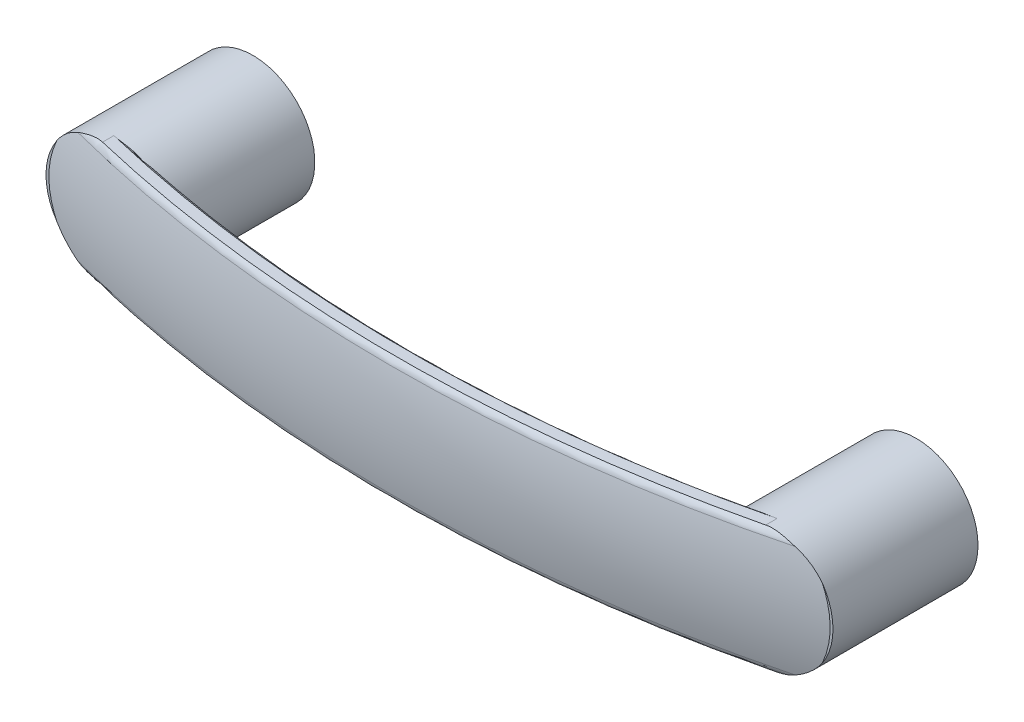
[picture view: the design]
ISO-10303-21;
HEADER;
FILE_DESCRIPTION(('STEP AP214'),'2;1');
FILE_NAME('part.step','',(''),(''),'','','');
FILE_SCHEMA(('AUTOMOTIVE_DESIGN { 1 0 10303 214 1 1 1 1 }'));
ENDSEC;
DATA;
#1=APPLICATION_CONTEXT('core data for automotive mechanical design processes');
#2=APPLICATION_PROTOCOL_DEFINITION('international standard','automotive_design',2000,#1);
#3=PRODUCT_CONTEXT('',#1,'mechanical');
#4=PRODUCT('Part','Part','',(#3));
#5=PRODUCT_RELATED_PRODUCT_CATEGORY('part','',(#4));
#6=PRODUCT_DEFINITION_FORMATION('','',#4);
#7=PRODUCT_DEFINITION_CONTEXT('part definition',#1,'design');
#8=PRODUCT_DEFINITION('design','',#6,#7);
#9=PRODUCT_DEFINITION_SHAPE('','',#8);
#10=(LENGTH_UNIT() NAMED_UNIT(*) SI_UNIT(.MILLI.,.METRE.));
#11=(NAMED_UNIT(*) PLANE_ANGLE_UNIT() SI_UNIT($,.RADIAN.));
#12=(NAMED_UNIT(*) SI_UNIT($,.STERADIAN.) SOLID_ANGLE_UNIT());
#13=UNCERTAINTY_MEASURE_WITH_UNIT(LENGTH_MEASURE(1.E-05),#10,'distance_accuracy_value','');
#14=(GEOMETRIC_REPRESENTATION_CONTEXT(3) GLOBAL_UNCERTAINTY_ASSIGNED_CONTEXT((#13)) GLOBAL_UNIT_ASSIGNED_CONTEXT((#10,
#11,#12)) REPRESENTATION_CONTEXT('',''));
#15=CARTESIAN_POINT('',(0.,0.,0.));
#16=DIRECTION('',(0.,0.,1.));
#17=DIRECTION('',(1.,0.,0.));
#18=AXIS2_PLACEMENT_3D('',#15,#16,#17);
#19=CARTESIAN_POINT('',(-0.255140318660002,0.,0.));
#20=DIRECTION('',(0.,0.,1.));
#21=DIRECTION('',(0.,-1.,0.));
#22=AXIS2_PLACEMENT_3D('',#19,#20,#21);
#23=PLANE('',#22);
#24=CARTESIAN_POINT('',(0.,0.,0.));
#25=DIRECTION('',(0.,0.,-1.));
#26=DIRECTION('',(-1.,0.,0.));
#27=AXIS2_PLACEMENT_3D('',#24,#25,#26);
#28=CIRCLE('',#27,4.);
#29=CARTESIAN_POINT('',(-4.,0.,0.));
#30=VERTEX_POINT('',#29);
#31=EDGE_CURVE('E339',#30,#30,#28,.T.);
#32=ORIENTED_EDGE('',*,*,#31,.F.);
#33=EDGE_LOOP('',(#32));
#34=FACE_BOUND('',#33,.T.);
#35=CARTESIAN_POINT('',(0.,0.,0.));
#36=DIRECTION('',(0.,0.,1.));
#37=DIRECTION('',(-1.,0.,0.));
#38=AXIS2_PLACEMENT_3D('',#35,#36,#37);
#39=CIRCLE('',#38,14.);
#40=CARTESIAN_POINT('',(-14.,0.,0.));
#41=VERTEX_POINT('',#40);
#42=EDGE_CURVE('E210',#41,#41,#39,.T.);
#43=ORIENTED_EDGE('',*,*,#42,.F.);
#44=EDGE_LOOP('',(#43));
#45=FACE_BOUND('',#44,.T.);
#46=ADVANCED_FACE('F14',(#34,#45),#23,.F.);
#47=CARTESIAN_POINT('',(-0.255140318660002,0.,32.8));
#48=DIRECTION('',(0.,0.,1.));
#49=DIRECTION('',(0.,-1.,0.));
#50=AXIS2_PLACEMENT_3D('',#47,#48,#49);
#51=PLANE('',#50);
#52=CARTESIAN_POINT('',(0.,0.,32.8));
#53=DIRECTION('',(0.,0.,1.));
#54=DIRECTION('',(1.,0.,0.));
#55=AXIS2_PLACEMENT_3D('',#52,#53,#54);
#56=CIRCLE('',#55,14.);
#57=CARTESIAN_POINT('',(-11.5953620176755,-7.84522655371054,32.8));
#58=VERTEX_POINT('',#57);
#59=CARTESIAN_POINT('',(-11.5953620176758,7.8452265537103,32.8));
#60=VERTEX_POINT('',#59);
#61=EDGE_CURVE('E9',#58,#60,#56,.F.);
#62=ORIENTED_EDGE('',*,*,#61,.F.);
#63=CARTESIAN_POINT('',(-13.3490803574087,1.41218032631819E-13,32.8));
#64=CARTESIAN_POINT('',(-13.3490709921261,-0.569935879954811,32.8));
#65=CARTESIAN_POINT('',(-13.3215830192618,-1.14012000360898,32.8));
#66=CARTESIAN_POINT('',(-13.2123860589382,-2.27554882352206,32.8));
#67=CARTESIAN_POINT('',(-13.1306350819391,-2.84078935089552,32.8));
#68=CARTESIAN_POINT('',(-12.9149496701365,-3.9626413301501,32.8));
#69=CARTESIAN_POINT('',(-12.7808871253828,-4.51922808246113,32.8));
#70=CARTESIAN_POINT('',(-12.464044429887,-5.61855917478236,32.8));
#71=CARTESIAN_POINT('',(-12.2812397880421,-6.16129640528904,32.8));
#72=CARTESIAN_POINT('',(-11.8733813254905,-7.2239957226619,32.8));
#73=CARTESIAN_POINT('',(-11.648794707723,-7.74413795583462,32.8));
#74=CARTESIAN_POINT('',(-11.1605291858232,-8.76583164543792,32.8));
#75=CARTESIAN_POINT('',(-10.896833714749,-9.2673751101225,32.8));
#76=CARTESIAN_POINT('',(-10.0541492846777,-10.7414126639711,32.8));
#77=CARTESIAN_POINT('',(-9.42309640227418,-11.684483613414,32.8));
#78=CARTESIAN_POINT('',(-8.14542950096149,-13.3693211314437,32.8));
#79=CARTESIAN_POINT('',(-7.51184390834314,-14.1212333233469,32.8));
#80=CARTESIAN_POINT('',(-6.18084712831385,-15.5669262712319,32.8));
#81=CARTESIAN_POINT('',(-5.48339382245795,-16.2606680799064,32.8));
#82=CARTESIAN_POINT('',(-4.03645149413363,-17.5950112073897,32.8));
#83=CARTESIAN_POINT('',(-3.28683177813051,-18.2354695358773,32.8));
#84=CARTESIAN_POINT('',(-1.74707423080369,-19.4660253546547,32.8));
#85=CARTESIAN_POINT('',(-0.956920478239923,-20.056102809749,32.8));
#86=CARTESIAN_POINT('',(0.604773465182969,-21.1541493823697,32.8));
#87=CARTESIAN_POINT('',(1.37433478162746,-21.6649507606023,32.8));
#88=CARTESIAN_POINT('',(2.93671257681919,-22.6492343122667,32.8));
#89=CARTESIAN_POINT('',(3.72952536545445,-23.1227223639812,32.8));
#90=CARTESIAN_POINT('',(5.33522483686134,-24.0359010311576,32.8));
#91=CARTESIAN_POINT('',(6.14812840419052,-24.475561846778,32.8));
#92=CARTESIAN_POINT('',(7.79019304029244,-25.3233754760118,32.8));
#93=CARTESIAN_POINT('',(8.61935474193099,-25.7315270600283,32.8));
#94=CARTESIAN_POINT('',(10.2927492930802,-26.5193919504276,32.8));
#95=CARTESIAN_POINT('',(11.1370051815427,-26.899056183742,32.8));
#96=CARTESIAN_POINT('',(12.837113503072,-27.6313371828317,32.8));
#97=CARTESIAN_POINT('',(13.6929656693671,-27.9839545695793,32.8));
#98=CARTESIAN_POINT('',(15.4142797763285,-28.6639496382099,32.8));
#99=CARTESIAN_POINT('',(16.2797383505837,-28.9913358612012,32.8));
#100=CARTESIAN_POINT('',(18.0191662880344,-29.6227044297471,32.8));
#101=CARTESIAN_POINT('',(18.89313597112,-29.9266858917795,32.8));
#102=CARTESIAN_POINT('',(20.729997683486,-30.5399909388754,32.8));
#103=CARTESIAN_POINT('',(21.6936011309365,-30.8471826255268,32.8));
#104=CARTESIAN_POINT('',(23.6282781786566,-31.4371256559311,32.8));
#105=CARTESIAN_POINT('',(24.5993521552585,-31.7198757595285,32.8));
#106=CARTESIAN_POINT('',(27.522440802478,-32.5338826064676,32.8));
#107=CARTESIAN_POINT('',(29.4840840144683,-33.0308173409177,32.8));
#108=CARTESIAN_POINT('',(33.4278863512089,-33.9436771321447,32.8));
#109=CARTESIAN_POINT('',(35.4100635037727,-34.3595232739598,32.8));
#110=CARTESIAN_POINT('',(39.3882486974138,-35.1174744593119,32.8));
#111=CARTESIAN_POINT('',(41.3842557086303,-35.4595849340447,32.8));
#112=CARTESIAN_POINT('',(45.3917301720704,-36.0770097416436,32.8));
#113=CARTESIAN_POINT('',(47.4032241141,-36.3521509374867,32.8));
#114=CARTESIAN_POINT('',(51.4338330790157,-36.8392239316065,32.8));
#115=CARTESIAN_POINT('',(53.4529482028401,-37.0511548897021,32.8));
#116=CARTESIAN_POINT('',(57.4954781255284,-37.4152116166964,32.8));
#117=CARTESIAN_POINT('',(59.5188901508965,-37.5673683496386,32.8));
#118=CARTESIAN_POINT('',(63.5691860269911,-37.8144735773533,32.8));
#119=CARTESIAN_POINT('',(65.5960698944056,-37.9094217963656,32.8));
#120=CARTESIAN_POINT('',(69.9667812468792,-38.0540495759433,32.8));
#121=CARTESIAN_POINT('',(72.3109211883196,-38.0944031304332,32.8));
#122=CARTESIAN_POINT('',(76.9993547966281,-38.1016218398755,32.8));
#123=CARTESIAN_POINT('',(79.3436484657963,-38.0684852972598,32.8));
#124=CARTESIAN_POINT('',(84.0314425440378,-37.9279830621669,32.8));
#125=CARTESIAN_POINT('',(86.3749416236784,-37.8205726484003,32.8));
#126=CARTESIAN_POINT('',(91.0571697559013,-37.5292164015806,32.8));
#127=CARTESIAN_POINT('',(93.3958989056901,-37.3452721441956,32.8));
#128=CARTESIAN_POINT('',(98.063191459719,-36.8971222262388,32.8));
#129=CARTESIAN_POINT('',(100.39176300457,-36.633001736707,32.8));
#130=CARTESIAN_POINT('',(105.037852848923,-36.0185447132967,32.8));
#131=CARTESIAN_POINT('',(107.355370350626,-35.6682020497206,32.8));
#132=CARTESIAN_POINT('',(110.818275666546,-35.0720785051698,32.8));
#133=CARTESIAN_POINT('',(111.969830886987,-34.8617135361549,32.8));
#134=CARTESIAN_POINT('',(114.268106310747,-34.4161123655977,32.8));
#135=CARTESIAN_POINT('',(115.414826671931,-34.1808769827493,32.8));
#136=CARTESIAN_POINT('',(117.702376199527,-33.6841023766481,32.8));
#137=CARTESIAN_POINT('',(118.843206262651,-33.4225672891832,32.8));
#138=CARTESIAN_POINT('',(121.118039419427,-32.8714640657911,32.8));
#139=CARTESIAN_POINT('',(122.252042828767,-32.5818972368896,32.8));
#140=CARTESIAN_POINT('',(124.455555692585,-31.9879558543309,32.8));
#141=CARTESIAN_POINT('',(125.525458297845,-31.6850425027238,32.8));
#142=CARTESIAN_POINT('',(127.656605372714,-31.0501791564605,32.8));
#143=CARTESIAN_POINT('',(128.71785008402,-30.7182299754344,32.8));
#144=CARTESIAN_POINT('',(130.83057501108,-30.0228805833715,32.8));
#145=CARTESIAN_POINT('',(131.882050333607,-29.6594654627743,32.8));
#146=CARTESIAN_POINT('',(133.97269434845,-28.8987348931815,32.8));
#147=CARTESIAN_POINT('',(135.011863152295,-28.5014197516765,32.8));
#148=CARTESIAN_POINT('',(137.069942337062,-27.6720906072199,32.8));
#149=CARTESIAN_POINT('',(138.088930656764,-27.2402706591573,32.8));
#150=CARTESIAN_POINT('',(140.109212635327,-26.3366853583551,32.8));
#151=CARTESIAN_POINT('',(141.110504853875,-25.8649167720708,32.8));
#152=CARTESIAN_POINT('',(143.090291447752,-24.878045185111,32.8));
#153=CARTESIAN_POINT('',(144.068808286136,-24.3629874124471,32.8));
#154=CARTESIAN_POINT('',(145.998777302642,-23.2847161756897,32.8));
#155=CARTESIAN_POINT('',(146.950236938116,-22.7215161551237,32.8));
#156=CARTESIAN_POINT('',(148.55229757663,-21.710373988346,32.8));
#157=CARTESIAN_POINT('',(149.211155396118,-21.275504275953,32.8));
#158=CARTESIAN_POINT('',(150.508585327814,-20.376436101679,32.8));
#159=CARTESIAN_POINT('',(151.147158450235,-19.9122391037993,32.8));
#160=CARTESIAN_POINT('',(152.40114019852,-18.951580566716,32.8));
#161=CARTESIAN_POINT('',(153.016513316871,-18.4550725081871,32.8));
#162=CARTESIAN_POINT('',(154.21836783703,-17.4280855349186,32.8));
#163=CARTESIAN_POINT('',(154.804848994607,-16.8976063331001,32.8));
#164=CARTESIAN_POINT('',(155.94890990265,-15.7947763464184,32.8));
#165=CARTESIAN_POINT('',(156.506130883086,-15.222051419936,32.8));
#166=CARTESIAN_POINT('',(157.57775105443,-14.0374719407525,32.8));
#167=CARTESIAN_POINT('',(158.092144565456,-13.425612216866,32.8));
#168=CARTESIAN_POINT('',(159.067967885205,-12.1627900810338,32.8));
#169=CARTESIAN_POINT('',(159.529504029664,-11.5119103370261,32.8));
#170=CARTESIAN_POINT('',(160.390010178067,-10.1700444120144,32.8));
#171=CARTESIAN_POINT('',(160.789013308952,-9.47907973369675,32.8));
#172=CARTESIAN_POINT('',(161.396300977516,-8.28741752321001,32.8));
#173=CARTESIAN_POINT('',(161.624674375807,-7.79691203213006,32.8));
#174=CARTESIAN_POINT('',(162.043253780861,-6.79992921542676,32.8));
#175=CARTESIAN_POINT('',(162.233470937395,-6.29345660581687,32.8));
#176=CARTESIAN_POINT('',(162.57191600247,-5.267023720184,32.8));
#177=CARTESIAN_POINT('',(162.720174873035,-4.74707370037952,32.8));
#178=CARTESIAN_POINT('',(162.971585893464,-3.69631165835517,32.8));
#179=CARTESIAN_POINT('',(163.074737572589,-3.16549952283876,32.8));
#180=CARTESIAN_POINT('',(163.233854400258,-2.09362456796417,32.8));
#181=CARTESIAN_POINT('',(163.289539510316,-1.55251990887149,32.8));
#182=CARTESIAN_POINT('',(163.351218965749,-0.467470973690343,32.8));
#183=CARTESIAN_POINT('',(163.35721356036,0.0764732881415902,32.8));
#184=CARTESIAN_POINT('',(163.319348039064,1.16269814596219,32.8));
#185=CARTESIAN_POINT('',(163.275479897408,1.70497846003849,32.8));
#186=CARTESIAN_POINT('',(163.139047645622,2.78334261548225,32.8));
#187=CARTESIAN_POINT('',(163.046484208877,3.31942654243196,32.8));
#188=CARTESIAN_POINT('',(162.823369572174,4.34313329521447,32.8));
#189=CARTESIAN_POINT('',(162.696036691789,4.83146438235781,32.8));
#190=CARTESIAN_POINT('',(162.403985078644,5.79694207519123,32.8));
#191=CARTESIAN_POINT('',(162.239254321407,6.27408502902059,32.8));
#192=CARTESIAN_POINT('',(161.875391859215,7.21499047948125,32.8));
#193=CARTESIAN_POINT('',(161.676261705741,7.67875357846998,32.8));
#194=CARTESIAN_POINT('',(161.246701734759,8.59159576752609,32.8));
#195=CARTESIAN_POINT('',(161.016264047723,9.04067113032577,32.8));
#196=CARTESIAN_POINT('',(160.388824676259,10.1729247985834,32.8));
#197=CARTESIAN_POINT('',(159.971344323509,10.8448156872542,32.8));
#198=CARTESIAN_POINT('',(159.078525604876,12.1490720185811,32.8));
#199=CARTESIAN_POINT('',(158.603154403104,12.781414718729,32.8));
#200=CARTESIAN_POINT('',(157.603341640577,14.0083401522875,32.8));
#201=CARTESIAN_POINT('',(157.07878510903,14.6028286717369,32.8));
#202=CARTESIAN_POINT('',(155.989992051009,15.7538584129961,32.8));
#203=CARTESIAN_POINT('',(155.425762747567,16.3104065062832,32.8));
#204=CARTESIAN_POINT('',(154.346576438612,17.3115185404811,32.8));
#205=CARTESIAN_POINT('',(153.835951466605,17.7607820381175,32.8));
#206=CARTESIAN_POINT('',(152.793861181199,18.6345171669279,32.8));
#207=CARTESIAN_POINT('',(152.262392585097,19.0589848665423,32.8));
#208=CARTESIAN_POINT('',(150.640746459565,20.2978002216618,32.8));
#209=CARTESIAN_POINT('',(149.523733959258,21.0771911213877,32.8));
#210=CARTESIAN_POINT('',(147.23529441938,22.554585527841,32.8));
#211=CARTESIAN_POINT('',(146.063781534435,23.2524541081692,32.8));
#212=CARTESIAN_POINT('',(143.680776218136,24.5751352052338,32.8));
#213=CARTESIAN_POINT('',(142.469292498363,25.1999635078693,32.8));
#214=CARTESIAN_POINT('',(139.971181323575,26.4062983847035,32.8));
#215=CARTESIAN_POINT('',(138.683418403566,26.9854383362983,32.8));
#216=CARTESIAN_POINT('',(136.081761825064,28.0821553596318,32.8));
#217=CARTESIAN_POINT('',(134.767862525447,28.5997189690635,32.8));
#218=CARTESIAN_POINT('',(132.11853748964,29.5799471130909,32.8));
#219=CARTESIAN_POINT('',(130.783093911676,30.0425631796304,32.8));
#220=CARTESIAN_POINT('',(128.096054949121,30.9176678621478,32.8));
#221=CARTESIAN_POINT('',(126.74446063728,31.3301597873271,32.8));
#222=CARTESIAN_POINT('',(124.024012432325,32.1107093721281,32.8));
#223=CARTESIAN_POINT('',(122.655117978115,32.4786250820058,32.8));
#224=CARTESIAN_POINT('',(119.906721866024,33.1722897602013,32.8));
#225=CARTESIAN_POINT('',(118.527220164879,33.4980385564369,32.8));
#226=CARTESIAN_POINT('',(115.760207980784,34.1103915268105,32.8));
#227=CARTESIAN_POINT('',(114.372701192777,34.3970124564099,32.8));
#228=CARTESIAN_POINT('',(111.590654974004,34.9339283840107,32.8));
#229=CARTESIAN_POINT('',(110.19611531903,35.1842222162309,32.8));
#230=CARTESIAN_POINT('',(107.36024669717,35.6575528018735,32.8));
#231=CARTESIAN_POINT('',(105.918748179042,35.879571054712,32.8));
#232=CARTESIAN_POINT('',(103.030863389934,36.2894698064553,32.8));
#233=CARTESIAN_POINT('',(101.584476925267,36.4773489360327,32.8));
#234=CARTESIAN_POINT('',(98.6876621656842,36.8206304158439,32.8));
#235=CARTESIAN_POINT('',(97.2372333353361,36.9760282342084,32.8));
#236=CARTESIAN_POINT('',(94.3333383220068,37.2556469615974,32.8));
#237=CARTESIAN_POINT('',(92.8798720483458,37.3798669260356,32.8));
#238=CARTESIAN_POINT('',(89.9690191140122,37.5982888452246,32.8));
#239=CARTESIAN_POINT('',(88.5116298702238,37.692456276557,32.8));
#240=CARTESIAN_POINT('',(85.5952152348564,37.8513586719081,32.8));
#241=CARTESIAN_POINT('',(84.1361898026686,37.9160928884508,32.8));
#242=CARTESIAN_POINT('',(81.2172949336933,38.0166484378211,32.8));
#243=CARTESIAN_POINT('',(79.7574255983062,38.0524727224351,32.8));
#244=CARTESIAN_POINT('',(76.8372265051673,38.0955101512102,32.8));
#245=CARTESIAN_POINT('',(75.3768967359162,38.1027225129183,32.8));
#246=CARTESIAN_POINT('',(72.4566049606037,38.0885932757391,32.8));
#247=CARTESIAN_POINT('',(70.9966429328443,38.0672561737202,32.8));
#248=CARTESIAN_POINT('',(68.0774597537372,37.9958644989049,32.8));
#249=CARTESIAN_POINT('',(66.6182385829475,37.9458107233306,32.8));
#250=CARTESIAN_POINT('',(63.7009263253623,37.8165728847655,32.8));
#251=CARTESIAN_POINT('',(62.2428353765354,37.7373856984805,32.8));
#252=CARTESIAN_POINT('',(59.3286089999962,37.5492348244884,32.8));
#253=CARTESIAN_POINT('',(57.8724735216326,37.440271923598,32.8));
#254=CARTESIAN_POINT('',(54.9645370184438,37.1918095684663,32.8));
#255=CARTESIAN_POINT('',(53.5127329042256,37.0523463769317,32.8));
#256=CARTESIAN_POINT('',(50.6125665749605,36.741635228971,32.8));
#257=CARTESIAN_POINT('',(49.1642042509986,36.5703882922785,32.8));
#258=CARTESIAN_POINT('',(46.271999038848,36.1946525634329,32.8));
#259=CARTESIAN_POINT('',(44.8281555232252,35.9901686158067,32.8));
#260=CARTESIAN_POINT('',(41.9459159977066,35.546131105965,32.8));
#261=CARTESIAN_POINT('',(40.5075197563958,35.3065790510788,32.8));
#262=CARTESIAN_POINT('',(37.6693206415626,34.7959335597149,32.8));
#263=CARTESIAN_POINT('',(36.2693707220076,34.5256597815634,32.8));
#264=CARTESIAN_POINT('',(33.4774009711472,33.9470063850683,32.8));
#265=CARTESIAN_POINT('',(32.0853808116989,33.6386283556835,32.8));
#266=CARTESIAN_POINT('',(29.3103126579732,32.9806334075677,32.8));
#267=CARTESIAN_POINT('',(27.9272697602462,32.6309949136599,32.8));
#268=CARTESIAN_POINT('',(25.1731527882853,31.8870729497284,32.8));
#269=CARTESIAN_POINT('',(23.8020790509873,31.4927882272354,32.8));
#270=CARTESIAN_POINT('',(21.0770552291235,30.6560443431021,32.8));
#271=CARTESIAN_POINT('',(19.7230811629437,30.2136636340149,32.8));
#272=CARTESIAN_POINT('',(17.0338471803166,29.2752181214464,32.8));
#273=CARTESIAN_POINT('',(15.698586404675,28.7791557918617,32.8));
#274=CARTESIAN_POINT('',(13.0532964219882,27.7279498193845,32.8));
#275=CARTESIAN_POINT('',(11.743237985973,27.1728801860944,32.8));
#276=CARTESIAN_POINT('',(9.15306547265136,25.9958224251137,32.8));
#277=CARTESIAN_POINT('',(7.8729576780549,25.3738204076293,32.8));
#278=CARTESIAN_POINT('',(5.33952548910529,24.0477371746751,32.8));
#279=CARTESIAN_POINT('',(4.08658428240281,23.3429143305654,32.8));
#280=CARTESIAN_POINT('',(2.2476867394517,22.2201340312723,32.8));
#281=CARTESIAN_POINT('',(1.64157360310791,21.8350211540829,32.8));
#282=CARTESIAN_POINT('',(0.444933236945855,21.0413518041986,32.8));
#283=CARTESIAN_POINT('',(-0.145595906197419,20.6327982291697,32.8));
#284=CARTESIAN_POINT('',(-1.30561608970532,19.7927215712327,32.8));
#285=CARTESIAN_POINT('',(-1.87519782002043,19.3613240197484,32.8));
#286=CARTESIAN_POINT('',(-2.99323824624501,18.4720936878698,32.8));
#287=CARTESIAN_POINT('',(-3.54170088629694,18.0142658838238,32.8));
#288=CARTESIAN_POINT('',(-4.61329676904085,17.0709132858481,32.8));
#289=CARTESIAN_POINT('',(-5.1364568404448,16.5854190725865,32.8));
#290=CARTESIAN_POINT('',(-6.15345635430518,15.584767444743,32.8));
#291=CARTESIAN_POINT('',(-6.64730408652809,15.0696184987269,32.8));
#292=CARTESIAN_POINT('',(-7.54172178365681,14.0734871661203,32.8));
#293=CARTESIAN_POINT('',(-7.94629131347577,13.5961031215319,32.8));
#294=CARTESIAN_POINT('',(-8.72449174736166,12.6167150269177,32.8));
#295=CARTESIAN_POINT('',(-9.09812569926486,12.1147134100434,32.8));
#296=CARTESIAN_POINT('',(-9.8098475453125,11.0854158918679,32.8));
#297=CARTESIAN_POINT('',(-10.1479073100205,10.5581004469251,32.8));
#298=CARTESIAN_POINT('',(-10.7827309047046,9.47880542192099,32.8));
#299=CARTESIAN_POINT('',(-11.0794809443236,8.92681768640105,32.8));
#300=CARTESIAN_POINT('',(-11.6294364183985,7.79184869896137,32.8));
#301=CARTESIAN_POINT('',(-11.8819739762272,7.20854170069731,32.8));
#302=CARTESIAN_POINT('',(-12.3319156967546,6.02131813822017,32.8));
#303=CARTESIAN_POINT('',(-12.5293559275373,5.41741534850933,32.8));
#304=CARTESIAN_POINT('',(-12.8630031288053,4.1949872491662,32.8));
#305=CARTESIAN_POINT('',(-12.9994094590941,3.57651659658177,32.8));
#306=CARTESIAN_POINT('',(-13.2073334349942,2.3291085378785,32.8));
#307=CARTESIAN_POINT('',(-13.2789147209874,1.70018201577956,32.8));
#308=CARTESIAN_POINT('',(-13.3276159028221,0.891514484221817,32.8));
#309=CARTESIAN_POINT('',(-13.3356601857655,0.713322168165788,32.8));
#310=CARTESIAN_POINT('',(-13.3463940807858,0.356761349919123,32.8));
#311=CARTESIAN_POINT('',(-13.3490832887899,0.178392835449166,32.8));
#312=CARTESIAN_POINT('',(-13.3490803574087,1.41218032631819E-13,32.8));
#313=B_SPLINE_CURVE_WITH_KNOTS('',3,(#63,#64,#65,#66,#67,#68,#69,#70,#71,#72,#73,#74,#75,#76,
#77,#78,#79,#80,#81,#82,#83,#84,#85,#86,#87,#88,#89,#90,#91,#92,#93,#94,#95,#96,#97,#98,#99,
#100,#101,#102,#103,#104,#105,#106,#107,#108,#109,#110,#111,#112,#113,#114,#115,#116,#117,#118,
#119,#120,#121,#122,#123,#124,#125,#126,#127,#128,#129,#130,#131,#132,#133,#134,#135,#136,#137,
#138,#139,#140,#141,#142,#143,#144,#145,#146,#147,#148,#149,#150,#151,#152,#153,#154,#155,#156,
#157,#158,#159,#160,#161,#162,#163,#164,#165,#166,#167,#168,#169,#170,#171,#172,#173,#174,#175,
#176,#177,#178,#179,#180,#181,#182,#183,#184,#185,#186,#187,#188,#189,#190,#191,#192,#193,#194,
#195,#196,#197,#198,#199,#200,#201,#202,#203,#204,#205,#206,#207,#208,#209,#210,#211,#212,#213,
#214,#215,#216,#217,#218,#219,#220,#221,#222,#223,#224,#225,#226,#227,#228,#229,#230,#231,#232,
#233,#234,#235,#236,#237,#238,#239,#240,#241,#242,#243,#244,#245,#246,#247,#248,#249,#250,#251,
#252,#253,#254,#255,#256,#257,#258,#259,#260,#261,#262,#263,#264,#265,#266,#267,#268,#269,#270,
#271,#272,#273,#274,#275,#276,#277,#278,#279,#280,#281,#282,#283,#284,#285,#286,#287,#288,#289,
#290,#291,#292,#293,#294,#295,#296,#297,#298,#299,#300,#301,#302,#303,#304,#305,#306,#307,#308,
#309,#310,#311,#312),.UNSPECIFIED.,.T.,.F.,(4,2,2,2,2,2,2,2,2,2,2,2,2,2,2,2,2,2,2,2,2,2,2,2,2,2,
2,2,2,2,2,2,2,2,2,2,2,2,2,2,2,2,2,2,2,2,2,2,2,2,2,2,2,2,2,2,2,2,2,2,2,2,2,2,2,2,2,2,2,2,2,2,2,2,
2,2,2,2,2,2,2,2,2,2,2,2,2,2,2,2,2,2,2,2,2,2,2,2,2,2,2,2,2,2,2,2,2,2,2,2,2,2,2,2,2,2,2,2,2,2,2,2,
2,2,4),(0.,1.70958586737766,3.42049618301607,5.1356230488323,6.8516133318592,8.54945795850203,
10.2480238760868,13.6414142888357,16.5872705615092,19.535083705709,22.4905681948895,
25.4472225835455,28.2170459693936,30.9864321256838,33.7582306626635,36.5301373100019,
39.3067142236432,42.0832273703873,44.8587964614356,47.6344702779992,50.6682589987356,
53.7022015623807,59.7708382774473,65.8453517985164,71.9194177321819,78.0090241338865,
84.0987114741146,90.1852400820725,96.2717980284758,103.304071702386,110.336507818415,
117.373181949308,124.409711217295,131.438791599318,138.468371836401,141.979985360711,
145.491483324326,149.002429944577,152.513212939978,155.848705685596,159.184104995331,
162.52109346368,165.858051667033,169.177410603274,172.497038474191,175.813240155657,
179.12851880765,181.496129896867,183.863622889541,186.234603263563,188.605603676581,
191.000959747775,193.396632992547,195.787398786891,198.176893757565,199.798700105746,
201.420031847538,203.040164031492,204.660313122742,206.289955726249,207.919590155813,
209.549486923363,211.179361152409,212.691777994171,214.204681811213,215.717517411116,
217.230733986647,219.6000209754,221.970658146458,224.346981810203,226.722873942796,
228.762428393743,230.802305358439,234.883697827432,238.971752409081,243.058921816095,
247.29310261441,251.528207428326,255.767020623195,260.005553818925,264.25724806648,
268.508959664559,272.758844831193,277.008866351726,281.383919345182,285.759147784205,
290.134986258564,294.510957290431,298.891937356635,303.273028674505,307.653672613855,
312.034436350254,316.414510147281,320.794462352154,325.174884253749,329.555190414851,
333.930316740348,338.305302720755,342.679651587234,347.053812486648,351.330724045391,
355.607457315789,359.88643689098,364.165536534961,368.437758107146,372.709782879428,
376.976511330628,381.244126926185,385.553381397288,387.70727102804,389.860894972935,
392.003713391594,394.146129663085,396.286222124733,398.425706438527,400.301869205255,
402.177846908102,404.055297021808,405.933372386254,407.837744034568,409.740866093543,
411.637725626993,413.532720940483,414.067789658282,414.602898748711),.UNSPECIFIED.);
#314=EDGE_CURVE('E144',#60,#58,#313,.T.);
#315=ORIENTED_EDGE('',*,*,#314,.F.);
#316=EDGE_LOOP('',(#62,#315));
#317=FACE_BOUND('',#316,.T.);
#318=ADVANCED_FACE('F161',(#317),#51,.T.);
#319=CARTESIAN_POINT('',(150.25514031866,0.,32.8));
#320=DIRECTION('',(0.,0.,1.));
#321=DIRECTION('',(0.,-1.,0.));
#322=AXIS2_PLACEMENT_3D('',#319,#320,#321);
#323=PLANE('',#322);
#324=CARTESIAN_POINT('',(150.,0.,32.8));
#325=DIRECTION('',(0.,0.,1.));
#326=DIRECTION('',(1.,0.,0.));
#327=AXIS2_PLACEMENT_3D('',#324,#325,#326);
#328=CIRCLE('',#327,14.);
#329=CARTESIAN_POINT('',(161.595362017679,7.84522655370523,32.8));
#330=VERTEX_POINT('',#329);
#331=CARTESIAN_POINT('',(161.595362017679,-7.84522655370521,32.8));
#332=VERTEX_POINT('',#331);
#333=EDGE_CURVE('E249',#330,#332,#328,.F.);
#334=ORIENTED_EDGE('',*,*,#333,.F.);
#335=CARTESIAN_POINT('',(163.34908035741,1.41218032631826E-13,32.8));
#336=CARTESIAN_POINT('',(163.349070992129,0.56993587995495,32.8));
#337=CARTESIAN_POINT('',(163.321583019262,1.14012000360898,32.8));
#338=CARTESIAN_POINT('',(163.212386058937,2.275548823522,32.8));
#339=CARTESIAN_POINT('',(163.130635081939,2.84078935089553,32.8));
#340=CARTESIAN_POINT('',(162.914949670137,3.96264133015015,32.8));
#341=CARTESIAN_POINT('',(162.780887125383,4.51922808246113,32.8));
#342=CARTESIAN_POINT('',(162.464044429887,5.61855917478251,32.8));
#343=CARTESIAN_POINT('',(162.281239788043,6.16129640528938,32.8));
#344=CARTESIAN_POINT('',(161.873381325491,7.22399572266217,32.8));
#345=CARTESIAN_POINT('',(161.648794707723,7.74413795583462,32.8));
#346=CARTESIAN_POINT('',(161.160529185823,8.76583164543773,32.8));
#347=CARTESIAN_POINT('',(160.896833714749,9.26737511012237,32.8));
#348=CARTESIAN_POINT('',(160.054149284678,10.7414126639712,32.8));
#349=CARTESIAN_POINT('',(159.423096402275,11.6844836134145,32.8));
#350=CARTESIAN_POINT('',(158.145429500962,13.369321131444,32.8));
#351=CARTESIAN_POINT('',(157.511843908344,14.1212333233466,32.8));
#352=CARTESIAN_POINT('',(156.180847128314,15.5669262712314,32.8));
#353=CARTESIAN_POINT('',(155.483393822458,16.2606680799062,32.8));
#354=CARTESIAN_POINT('',(154.036451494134,17.5950112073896,32.8));
#355=CARTESIAN_POINT('',(153.286831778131,18.235469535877,32.8));
#356=CARTESIAN_POINT('',(151.747074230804,19.4660253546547,32.8));
#357=CARTESIAN_POINT('',(150.95692047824,20.0561028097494,32.8));
#358=CARTESIAN_POINT('',(149.395226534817,21.1541493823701,32.8));
#359=CARTESIAN_POINT('',(148.625665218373,21.6649507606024,32.8));
#360=CARTESIAN_POINT('',(147.063287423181,22.6492343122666,32.8));
#361=CARTESIAN_POINT('',(146.270474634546,23.1227223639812,32.8));
#362=CARTESIAN_POINT('',(144.664775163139,24.0359010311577,32.8));
#363=CARTESIAN_POINT('',(143.851871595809,24.475561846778,32.8));
#364=CARTESIAN_POINT('',(142.209806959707,25.3233754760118,32.8));
#365=CARTESIAN_POINT('',(141.380645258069,25.7315270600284,32.8));
#366=CARTESIAN_POINT('',(139.70725070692,26.5193919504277,32.8));
#367=CARTESIAN_POINT('',(138.862994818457,26.8990561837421,32.8));
#368=CARTESIAN_POINT('',(137.162886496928,27.6313371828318,32.8));
#369=CARTESIAN_POINT('',(136.307034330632,27.9839545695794,32.8));
#370=CARTESIAN_POINT('',(134.585720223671,28.66394963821,32.8));
#371=CARTESIAN_POINT('',(133.720261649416,28.9913358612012,32.8));
#372=CARTESIAN_POINT('',(131.980833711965,29.6227044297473,32.8));
#373=CARTESIAN_POINT('',(131.10686402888,29.9266858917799,32.8));
#374=CARTESIAN_POINT('',(129.270002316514,30.5399909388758,32.8));
#375=CARTESIAN_POINT('',(128.306398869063,30.847182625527,32.8));
#376=CARTESIAN_POINT('',(126.371721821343,31.4371256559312,32.8));
#377=CARTESIAN_POINT('',(125.400647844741,31.7198757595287,32.8));
#378=CARTESIAN_POINT('',(122.477559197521,32.5338826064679,32.8));
#379=CARTESIAN_POINT('',(120.515915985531,33.0308173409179,32.8));
#380=CARTESIAN_POINT('',(116.57211364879,33.9436771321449,32.8));
#381=CARTESIAN_POINT('',(114.589936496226,34.35952327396,32.8));
#382=CARTESIAN_POINT('',(110.611751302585,35.1174744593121,32.8));
#383=CARTESIAN_POINT('',(108.615744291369,35.4595849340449,32.8));
#384=CARTESIAN_POINT('',(104.608269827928,36.0770097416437,32.8));
#385=CARTESIAN_POINT('',(102.596775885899,36.3521509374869,32.8));
#386=CARTESIAN_POINT('',(98.5661669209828,36.8392239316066,32.8));
#387=CARTESIAN_POINT('',(96.5470517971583,37.0511548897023,32.8));
#388=CARTESIAN_POINT('',(92.5045218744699,37.4152116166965,32.8));
#389=CARTESIAN_POINT('',(90.4811098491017,37.5673683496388,32.8));
#390=CARTESIAN_POINT('',(86.430813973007,37.8144735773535,32.8));
#391=CARTESIAN_POINT('',(84.4039301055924,37.9094217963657,32.8));
#392=CARTESIAN_POINT('',(80.0332187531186,38.0540495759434,32.8));
#393=CARTESIAN_POINT('',(77.6890788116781,38.0944031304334,32.8));
#394=CARTESIAN_POINT('',(73.0006452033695,38.1016218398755,32.8));
#395=CARTESIAN_POINT('',(70.6563515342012,38.0684852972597,32.8));
#396=CARTESIAN_POINT('',(65.9685574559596,37.9279830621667,32.8));
#397=CARTESIAN_POINT('',(63.6250583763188,37.8205726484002,32.8));
#398=CARTESIAN_POINT('',(58.9428302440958,37.5292164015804,32.8));
#399=CARTESIAN_POINT('',(56.6041010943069,37.3452721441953,32.8));
#400=CARTESIAN_POINT('',(51.936808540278,36.8971222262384,32.8));
#401=CARTESIAN_POINT('',(49.6082369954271,36.6330017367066,32.8));
#402=CARTESIAN_POINT('',(44.9621471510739,36.0185447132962,32.8));
#403=CARTESIAN_POINT('',(42.6446296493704,35.66820204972,32.8));
#404=CARTESIAN_POINT('',(39.1817243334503,35.0720785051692,32.8));
#405=CARTESIAN_POINT('',(38.0301691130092,34.8617135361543,32.8));
#406=CARTESIAN_POINT('',(35.731893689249,34.416112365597,32.8));
#407=CARTESIAN_POINT('',(34.5851733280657,34.1808769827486,32.8));
#408=CARTESIAN_POINT('',(32.2976238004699,33.6841023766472,32.8));
#409=CARTESIAN_POINT('',(31.1567937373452,33.4225672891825,32.8));
#410=CARTESIAN_POINT('',(28.8819605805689,32.8714640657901,32.8));
#411=CARTESIAN_POINT('',(27.7479571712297,32.5818972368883,32.8));
#412=CARTESIAN_POINT('',(25.544444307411,31.9879558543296,32.8));
#413=CARTESIAN_POINT('',(24.4745417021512,31.6850425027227,32.8));
#414=CARTESIAN_POINT('',(22.3433946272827,31.0501791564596,32.8));
#415=CARTESIAN_POINT('',(21.2821499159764,30.7182299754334,32.8));
#416=CARTESIAN_POINT('',(19.1694249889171,30.0228805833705,32.8));
#417=CARTESIAN_POINT('',(18.11794966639,29.6594654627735,32.8));
#418=CARTESIAN_POINT('',(16.0273056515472,28.8987348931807,32.8));
#419=CARTESIAN_POINT('',(14.9881368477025,28.5014197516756,32.8));
#420=CARTESIAN_POINT('',(12.9300576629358,27.6720906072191,32.8));
#421=CARTESIAN_POINT('',(11.9110693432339,27.2402706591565,32.8));
#422=CARTESIAN_POINT('',(9.89078736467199,26.3366853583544,32.8));
#423=CARTESIAN_POINT('',(8.88949514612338,25.8649167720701,32.8));
#424=CARTESIAN_POINT('',(6.90970855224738,24.8780451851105,32.8));
#425=CARTESIAN_POINT('',(5.93119171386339,24.3629874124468,32.8));
#426=CARTESIAN_POINT('',(4.00122269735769,23.2847161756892,32.8));
#427=CARTESIAN_POINT('',(3.04976306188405,22.7215161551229,32.8));
#428=CARTESIAN_POINT('',(1.44770242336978,21.7103739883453,32.8));
#429=CARTESIAN_POINT('',(0.788844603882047,21.2755042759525,32.8));
#430=CARTESIAN_POINT('',(-0.508585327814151,20.3764361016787,32.8));
#431=CARTESIAN_POINT('',(-1.14715845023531,19.9122391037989,32.8));
#432=CARTESIAN_POINT('',(-2.40114019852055,18.9515805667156,32.8));
#433=CARTESIAN_POINT('',(-3.01651331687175,18.4550725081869,32.8));
#434=CARTESIAN_POINT('',(-4.21836783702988,17.428085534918,32.8));
#435=CARTESIAN_POINT('',(-4.80484899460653,16.8976063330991,32.8));
#436=CARTESIAN_POINT('',(-5.94890990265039,15.7947763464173,32.8));
#437=CARTESIAN_POINT('',(-6.50613088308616,15.2220514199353,32.8));
#438=CARTESIAN_POINT('',(-7.57775105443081,14.037471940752,32.8));
#439=CARTESIAN_POINT('',(-8.09214456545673,13.4256122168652,32.8));
#440=CARTESIAN_POINT('',(-9.06796788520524,12.162790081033,32.8));
#441=CARTESIAN_POINT('',(-9.52950402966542,11.5119103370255,32.8));
#442=CARTESIAN_POINT('',(-10.3900101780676,10.1700444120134,32.8));
#443=CARTESIAN_POINT('',(-10.7890133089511,9.47907973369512,32.8));
#444=CARTESIAN_POINT('',(-11.3963009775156,8.2874175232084,32.8));
#445=CARTESIAN_POINT('',(-11.6246743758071,7.79691203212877,32.8));
#446=CARTESIAN_POINT('',(-12.0432537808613,6.79992921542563,32.8));
#447=CARTESIAN_POINT('',(-12.2334709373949,6.29345660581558,32.8));
#448=CARTESIAN_POINT('',(-12.5719160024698,5.26702372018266,32.8));
#449=CARTESIAN_POINT('',(-12.7201748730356,4.74707370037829,32.8));
#450=CARTESIAN_POINT('',(-12.9715858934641,3.6963116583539,32.8));
#451=CARTESIAN_POINT('',(-13.0747375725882,3.16549952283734,32.8));
#452=CARTESIAN_POINT('',(-13.2338544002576,2.09362456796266,32.8));
#453=CARTESIAN_POINT('',(-13.2895395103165,1.55251990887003,32.8));
#454=CARTESIAN_POINT('',(-13.351218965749,0.467470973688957,32.8));
#455=CARTESIAN_POINT('',(-13.3572135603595,-0.0764732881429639,32.8));
#456=CARTESIAN_POINT('',(-13.3193480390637,-1.16269814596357,32.8));
#457=CARTESIAN_POINT('',(-13.275479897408,-1.70497846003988,32.8));
#458=CARTESIAN_POINT('',(-13.1390476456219,-2.78334261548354,32.8));
#459=CARTESIAN_POINT('',(-13.0464842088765,-3.31942654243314,32.8));
#460=CARTESIAN_POINT('',(-12.823369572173,-4.34313329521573,32.8));
#461=CARTESIAN_POINT('',(-12.6960366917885,-4.83146438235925,32.8));
#462=CARTESIAN_POINT('',(-12.4039850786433,-5.79694207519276,32.8));
#463=CARTESIAN_POINT('',(-12.2392543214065,-6.27408502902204,32.8));
#464=CARTESIAN_POINT('',(-11.8753918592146,-7.21499047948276,32.8));
#465=CARTESIAN_POINT('',(-11.6762617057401,-7.67875357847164,32.8));
#466=CARTESIAN_POINT('',(-11.2467017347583,-8.59159576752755,32.8));
#467=CARTESIAN_POINT('',(-11.0162640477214,-9.04067113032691,32.8));
#468=CARTESIAN_POINT('',(-10.3888246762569,-10.1729247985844,32.8));
#469=CARTESIAN_POINT('',(-9.97134432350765,-10.8448156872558,32.8));
#470=CARTESIAN_POINT('',(-9.0785256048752,-12.1490720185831,32.8));
#471=CARTESIAN_POINT('',(-8.60315440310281,-12.7814147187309,32.8));
#472=CARTESIAN_POINT('',(-7.60334164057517,-14.0083401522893,32.8));
#473=CARTESIAN_POINT('',(-7.07878510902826,-14.6028286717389,32.8));
#474=CARTESIAN_POINT('',(-5.98999205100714,-15.7538584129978,32.8));
#475=CARTESIAN_POINT('',(-5.42576274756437,-16.3104065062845,32.8));
#476=CARTESIAN_POINT('',(-4.34657643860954,-17.3115185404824,32.8));
#477=CARTESIAN_POINT('',(-3.8359514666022,-17.7607820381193,32.8));
#478=CARTESIAN_POINT('',(-2.79386118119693,-18.6345171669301,32.8));
#479=CARTESIAN_POINT('',(-2.26239258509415,-19.0589848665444,32.8));
#480=CARTESIAN_POINT('',(-0.640746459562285,-20.2978002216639,32.8));
#481=CARTESIAN_POINT('',(0.476266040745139,-21.0771911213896,32.8));
#482=CARTESIAN_POINT('',(2.76470558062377,-22.554585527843,32.8));
#483=CARTESIAN_POINT('',(3.93621846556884,-23.2524541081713,32.8));
#484=CARTESIAN_POINT('',(6.31922378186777,-24.5751352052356,32.8));
#485=CARTESIAN_POINT('',(7.53070750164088,-25.1999635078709,32.8));
#486=CARTESIAN_POINT('',(10.0288186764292,-26.4062983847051,32.8));
#487=CARTESIAN_POINT('',(11.3165815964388,-26.9854383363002,32.8));
#488=CARTESIAN_POINT('',(13.9182381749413,-28.082155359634,32.8));
#489=CARTESIAN_POINT('',(15.2321374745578,-28.5997189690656,32.8));
#490=CARTESIAN_POINT('',(17.8814625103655,-29.579947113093,32.8));
#491=CARTESIAN_POINT('',(19.2169060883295,-30.0425631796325,32.8));
#492=CARTESIAN_POINT('',(21.9039450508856,-30.9176678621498,32.8));
#493=CARTESIAN_POINT('',(23.2555393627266,-31.3301597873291,32.8));
#494=CARTESIAN_POINT('',(25.9759875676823,-32.11070937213,32.8));
#495=CARTESIAN_POINT('',(27.3448820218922,-32.4786250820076,32.8));
#496=CARTESIAN_POINT('',(30.0932781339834,-33.1722897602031,32.8));
#497=CARTESIAN_POINT('',(31.4727798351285,-33.4980385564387,32.8));
#498=CARTESIAN_POINT('',(34.2397920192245,-34.1103915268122,32.8));
#499=CARTESIAN_POINT('',(35.6272988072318,-34.3970124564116,32.8));
#500=CARTESIAN_POINT('',(38.4093450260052,-34.9339283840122,32.8));
#501=CARTESIAN_POINT('',(39.8038846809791,-35.1842222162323,32.8));
#502=CARTESIAN_POINT('',(42.6397533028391,-35.6575528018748,32.8));
#503=CARTESIAN_POINT('',(44.0812518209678,-35.8795710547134,32.8));
#504=CARTESIAN_POINT('',(46.9691366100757,-36.2894698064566,32.8));
#505=CARTESIAN_POINT('',(48.4155230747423,-36.4773489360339,32.8));
#506=CARTESIAN_POINT('',(51.3123378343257,-36.820630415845,32.8));
#507=CARTESIAN_POINT('',(52.7627666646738,-36.9760282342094,32.8));
#508=CARTESIAN_POINT('',(55.6666616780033,-37.2556469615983,32.8));
#509=CARTESIAN_POINT('',(57.1201279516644,-37.3798669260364,32.8));
#510=CARTESIAN_POINT('',(60.0309808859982,-37.5982888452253,32.8));
#511=CARTESIAN_POINT('',(61.4883701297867,-37.6924562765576,32.8));
#512=CARTESIAN_POINT('',(64.4047847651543,-37.8513586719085,32.8));
#513=CARTESIAN_POINT('',(65.8638101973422,-37.9160928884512,32.8));
#514=CARTESIAN_POINT('',(68.7827050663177,-38.0166484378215,32.8));
#515=CARTESIAN_POINT('',(70.2425744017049,-38.0524727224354,32.8));
#516=CARTESIAN_POINT('',(73.1627734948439,-38.0955101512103,32.8));
#517=CARTESIAN_POINT('',(74.6231032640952,-38.1027225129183,32.8));
#518=CARTESIAN_POINT('',(77.5433950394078,-38.088593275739,32.8));
#519=CARTESIAN_POINT('',(79.0033570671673,-38.06725617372,32.8));
#520=CARTESIAN_POINT('',(81.9225402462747,-37.9958644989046,32.8));
#521=CARTESIAN_POINT('',(83.3817614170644,-37.9458107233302,32.8));
#522=CARTESIAN_POINT('',(86.2990736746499,-37.8165728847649,32.8));
#523=CARTESIAN_POINT('',(87.7571646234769,-37.7373856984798,32.8));
#524=CARTESIAN_POINT('',(90.6713910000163,-37.5492348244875,32.8));
#525=CARTESIAN_POINT('',(92.12752647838,-37.440271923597,32.8));
#526=CARTESIAN_POINT('',(95.0354629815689,-37.1918095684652,32.8));
#527=CARTESIAN_POINT('',(96.4872670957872,-37.0523463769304,32.8));
#528=CARTESIAN_POINT('',(99.3874334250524,-36.7416352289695,32.8));
#529=CARTESIAN_POINT('',(100.835795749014,-36.570388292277,32.8));
#530=CARTESIAN_POINT('',(103.728000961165,-36.1946525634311,32.8));
#531=CARTESIAN_POINT('',(105.171844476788,-35.9901686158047,32.8));
#532=CARTESIAN_POINT('',(108.054084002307,-35.5461311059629,32.8));
#533=CARTESIAN_POINT('',(109.492480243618,-35.3065790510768,32.8));
#534=CARTESIAN_POINT('',(112.330679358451,-34.7959335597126,32.8));
#535=CARTESIAN_POINT('',(113.730629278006,-34.5256597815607,32.8));
#536=CARTESIAN_POINT('',(116.522599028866,-33.9470063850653,32.8));
#537=CARTESIAN_POINT('',(117.914619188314,-33.6386283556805,32.8));
#538=CARTESIAN_POINT('',(120.68968734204,-32.9806334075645,32.8));
#539=CARTESIAN_POINT('',(122.072730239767,-32.6309949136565,32.8));
#540=CARTESIAN_POINT('',(124.826847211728,-31.8870729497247,32.8));
#541=CARTESIAN_POINT('',(126.197920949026,-31.4927882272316,32.8));
#542=CARTESIAN_POINT('',(128.922944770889,-30.6560443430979,32.8));
#543=CARTESIAN_POINT('',(130.276918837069,-30.2136636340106,32.8));
#544=CARTESIAN_POINT('',(132.966152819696,-29.2752181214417,32.8));
#545=CARTESIAN_POINT('',(134.301413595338,-28.7791557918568,32.8));
#546=CARTESIAN_POINT('',(136.946703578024,-27.7279498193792,32.8));
#547=CARTESIAN_POINT('',(138.256762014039,-27.1728801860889,32.8));
#548=CARTESIAN_POINT('',(140.846934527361,-25.9958224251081,32.8));
#549=CARTESIAN_POINT('',(142.127042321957,-25.3738204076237,32.8));
#550=CARTESIAN_POINT('',(144.660474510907,-24.0477371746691,32.8));
#551=CARTESIAN_POINT('',(145.913415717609,-23.3429143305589,32.8));
#552=CARTESIAN_POINT('',(147.75231326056,-22.2201340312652,32.8));
#553=CARTESIAN_POINT('',(148.358426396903,-21.8350211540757,32.8));
#554=CARTESIAN_POINT('',(149.555066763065,-21.0413518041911,32.8));
#555=CARTESIAN_POINT('',(150.145595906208,-20.632798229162,32.8));
#556=CARTESIAN_POINT('',(151.305616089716,-19.7927215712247,32.8));
#557=CARTESIAN_POINT('',(151.875197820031,-19.3613240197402,32.8));
#558=CARTESIAN_POINT('',(152.993238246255,-18.4720936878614,32.8));
#559=CARTESIAN_POINT('',(153.541700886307,-18.0142658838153,32.8));
#560=CARTESIAN_POINT('',(154.613296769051,-17.0709132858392,32.8));
#561=CARTESIAN_POINT('',(155.136456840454,-16.5854190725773,32.8));
#562=CARTESIAN_POINT('',(156.153456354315,-15.5847674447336,32.8));
#563=CARTESIAN_POINT('',(156.647304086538,-15.0696184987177,32.8));
#564=CARTESIAN_POINT('',(157.541721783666,-14.073487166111,32.8));
#565=CARTESIAN_POINT('',(157.946291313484,-13.5961031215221,32.8));
#566=CARTESIAN_POINT('',(158.724491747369,-12.6167150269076,32.8));
#567=CARTESIAN_POINT('',(159.098125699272,-12.1147134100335,32.8));
#568=CARTESIAN_POINT('',(159.809847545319,-11.0854158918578,32.8));
#569=CARTESIAN_POINT('',(160.147907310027,-10.5581004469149,32.8));
#570=CARTESIAN_POINT('',(160.78273090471,-9.47880542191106,32.8));
#571=CARTESIAN_POINT('',(161.07948094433,-8.92681768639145,32.8));
#572=CARTESIAN_POINT('',(161.629436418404,-7.79184869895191,32.8));
#573=CARTESIAN_POINT('',(161.881973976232,-7.20854170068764,32.8));
#574=CARTESIAN_POINT('',(162.331915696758,-6.02131813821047,32.8));
#575=CARTESIAN_POINT('',(162.52935592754,-5.41741534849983,32.8));
#576=CARTESIAN_POINT('',(162.863003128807,-4.19498724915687,32.8));
#577=CARTESIAN_POINT('',(162.999409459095,-3.57651659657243,32.8));
#578=CARTESIAN_POINT('',(163.207333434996,-2.3291085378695,32.8));
#579=CARTESIAN_POINT('',(163.278914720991,-1.70018201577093,32.8));
#580=CARTESIAN_POINT('',(163.327615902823,-0.891514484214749,32.8));
#581=CARTESIAN_POINT('',(163.335660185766,-0.713322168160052,32.8));
#582=CARTESIAN_POINT('',(163.346394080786,-0.356761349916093,32.8));
#583=CARTESIAN_POINT('',(163.349083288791,-0.17839283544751,32.8));
#584=CARTESIAN_POINT('',(163.34908035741,1.41218032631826E-13,32.8));
#585=B_SPLINE_CURVE_WITH_KNOTS('',3,(#335,#336,#337,#338,#339,#340,#341,#342,#343,#344,#345,
#346,#347,#348,#349,#350,#351,#352,#353,#354,#355,#356,#357,#358,#359,#360,#361,#362,#363,#364,
#365,#366,#367,#368,#369,#370,#371,#372,#373,#374,#375,#376,#377,#378,#379,#380,#381,#382,#383,
#384,#385,#386,#387,#388,#389,#390,#391,#392,#393,#394,#395,#396,#397,#398,#399,#400,#401,#402,
#403,#404,#405,#406,#407,#408,#409,#410,#411,#412,#413,#414,#415,#416,#417,#418,#419,#420,#421,
#422,#423,#424,#425,#426,#427,#428,#429,#430,#431,#432,#433,#434,#435,#436,#437,#438,#439,#440,
#441,#442,#443,#444,#445,#446,#447,#448,#449,#450,#451,#452,#453,#454,#455,#456,#457,#458,#459,
#460,#461,#462,#463,#464,#465,#466,#467,#468,#469,#470,#471,#472,#473,#474,#475,#476,#477,#478,
#479,#480,#481,#482,#483,#484,#485,#486,#487,#488,#489,#490,#491,#492,#493,#494,#495,#496,#497,
#498,#499,#500,#501,#502,#503,#504,#505,#506,#507,#508,#509,#510,#511,#512,#513,#514,#515,#516,
#517,#518,#519,#520,#521,#522,#523,#524,#525,#526,#527,#528,#529,#530,#531,#532,#533,#534,#535,
#536,#537,#538,#539,#540,#541,#542,#543,#544,#545,#546,#547,#548,#549,#550,#551,#552,#553,#554,
#555,#556,#557,#558,#559,#560,#561,#562,#563,#564,#565,#566,#567,#568,#569,#570,#571,#572,#573,
#574,#575,#576,#577,#578,#579,#580,#581,#582,#583,#584),.UNSPECIFIED.,.T.,.F.,(4,2,2,2,2,2,2,2,
2,2,2,2,2,2,2,2,2,2,2,2,2,2,2,2,2,2,2,2,2,2,2,2,2,2,2,2,2,2,2,2,2,2,2,2,2,2,2,2,2,2,2,2,2,2,2,2,
2,2,2,2,2,2,2,2,2,2,2,2,2,2,2,2,2,2,2,2,2,2,2,2,2,2,2,2,2,2,2,2,2,2,2,2,2,2,2,2,2,2,2,2,2,2,2,2,
2,2,2,2,2,2,2,2,2,2,2,2,2,2,2,2,2,2,2,2,4),(0.,1.70958586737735,3.42049618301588,
5.13562304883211,6.85161333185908,8.54945795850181,10.2480238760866,13.6414142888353,
16.5872705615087,19.5350837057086,22.4905681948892,25.4472225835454,28.2170459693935,
30.9864321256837,33.7582306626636,36.5301373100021,39.3067142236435,42.0832273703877,
44.8587964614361,47.6344702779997,50.6682589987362,53.7022015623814,59.7708382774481,
65.8453517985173,71.9194177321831,78.0090241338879,84.0987114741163,90.1852400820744,
96.2717980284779,103.304071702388,110.336507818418,117.37318194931,124.409711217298,
131.438791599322,138.468371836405,141.979985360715,145.49148332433,149.002429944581,
152.513212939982,155.8487056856,159.184104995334,162.521093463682,165.858051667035,
169.177410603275,172.497038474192,175.813240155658,179.128518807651,181.496129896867,
183.863622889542,186.234603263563,188.605603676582,191.000959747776,193.396632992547,
195.787398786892,198.176893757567,199.798700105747,201.420031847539,203.040164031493,
204.660313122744,206.28995572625,207.919590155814,209.549486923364,211.17936115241,
212.691777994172,214.204681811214,215.717517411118,217.230733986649,219.600020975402,
221.97065814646,224.346981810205,226.722873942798,228.762428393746,230.802305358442,
234.883697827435,238.971752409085,243.0589218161,247.293102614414,251.528207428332,
255.767020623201,260.005553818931,264.257248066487,268.508959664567,272.758844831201,
277.008866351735,281.383919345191,285.759147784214,290.134986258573,294.510957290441,
298.891937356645,303.273028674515,307.653672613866,312.034436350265,316.414510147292,
320.794462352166,325.174884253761,329.555190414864,333.93031674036,338.305302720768,
342.679651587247,347.053812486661,351.330724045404,355.607457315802,359.886436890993,
364.165536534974,368.437758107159,372.709782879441,376.976511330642,381.244126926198,
385.5533813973,387.707271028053,389.860894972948,392.003713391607,394.146129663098,
396.286222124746,398.42570643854,400.301869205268,402.177846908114,404.055297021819,
405.933372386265,407.837744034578,409.740866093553,411.637725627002,413.532720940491,
414.067789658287,414.602898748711),.UNSPECIFIED.);
#586=EDGE_CURVE('E152',#332,#330,#585,.T.);
#587=ORIENTED_EDGE('',*,*,#586,.F.);
#588=EDGE_LOOP('',(#334,#587));
#589=FACE_BOUND('',#588,.T.);
#590=ADVANCED_FACE('F166',(#589),#323,.T.);
#591=CARTESIAN_POINT('',(150.25514031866,0.,0.));
#592=DIRECTION('',(0.,0.,1.));
#593=DIRECTION('',(0.,-1.,0.));
#594=AXIS2_PLACEMENT_3D('',#591,#592,#593);
#595=PLANE('',#594);
#596=CARTESIAN_POINT('',(150.,0.,0.));
#597=DIRECTION('',(0.,0.,-1.));
#598=DIRECTION('',(-1.,0.,0.));
#599=AXIS2_PLACEMENT_3D('',#596,#597,#598);
#600=CIRCLE('',#599,4.);
#601=CARTESIAN_POINT('',(146.,0.,0.));
#602=VERTEX_POINT('',#601);
#603=EDGE_CURVE('E228',#602,#602,#600,.T.);
#604=ORIENTED_EDGE('',*,*,#603,.F.);
#605=EDGE_LOOP('',(#604));
#606=FACE_BOUND('',#605,.T.);
#607=CARTESIAN_POINT('',(150.,0.,0.));
#608=DIRECTION('',(0.,0.,1.));
#609=DIRECTION('',(1.,0.,0.));
#610=AXIS2_PLACEMENT_3D('',#607,#608,#609);
#611=CIRCLE('',#610,14.);
#612=CARTESIAN_POINT('',(164.,0.,0.));
#613=VERTEX_POINT('',#612);
#614=EDGE_CURVE('E22',#613,#613,#611,.F.);
#615=ORIENTED_EDGE('',*,*,#614,.T.);
#616=EDGE_LOOP('',(#615));
#617=FACE_BOUND('',#616,.T.);
#618=ADVANCED_FACE('F271',(#606,#617),#595,.F.);
#619=CARTESIAN_POINT('',(75.,0.,-280.25));
#620=DIRECTION('',(0.,1.,0.));
#621=DIRECTION('',(-1.,0.,0.));
#622=AXIS2_PLACEMENT_3D('',#619,#620,#621);
#623=TOROIDAL_SURFACE('',#622,339.800563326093,24.0485063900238);
#624=CARTESIAN_POINT('',(75.,-12.3536847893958,-280.25));
#625=DIRECTION('',(0.,1.,0.));
#626=DIRECTION('',(-1.,0.,0.));
#627=AXIS2_PLACEMENT_3D('',#624,#625,#626);
#628=CIRCLE('',#627,319.167649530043);
#629=CARTESIAN_POINT('',(6.58684083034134,-12.3536847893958,31.4993033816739));
#630=VERTEX_POINT('',#629);
#631=CARTESIAN_POINT('',(143.413159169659,-12.3536847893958,31.499303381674));
#632=VERTEX_POINT('',#631);
#633=EDGE_CURVE('E120',#630,#632,#628,.T.);
#634=ORIENTED_EDGE('',*,*,#633,.F.);
#635=CARTESIAN_POINT('',(6.58646571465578,-12.3538847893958,31.4993436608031));
#636=CARTESIAN_POINT('',(6.93523691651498,-12.1679719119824,31.4618915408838));
#637=CARTESIAN_POINT('',(7.27532480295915,-11.9676565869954,31.4167152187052));
#638=CARTESIAN_POINT('',(7.93599290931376,-11.540125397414,31.3145631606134));
#639=CARTESIAN_POINT('',(8.25658535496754,-11.3129266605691,31.2575949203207));
#640=CARTESIAN_POINT('',(8.87630742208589,-10.8334948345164,31.135502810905));
#641=CARTESIAN_POINT('',(9.17545489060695,-10.5812829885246,31.0703858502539));
#642=CARTESIAN_POINT('',(9.75108282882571,-10.0533037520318,30.9353271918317));
#643=CARTESIAN_POINT('',(10.0275596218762,-9.77753255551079,30.8653847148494));
#644=CARTESIAN_POINT('',(10.5558843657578,-9.2046125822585,30.7239468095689));
#645=CARTESIAN_POINT('',(10.807773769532,-8.90750130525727,30.6524542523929));
#646=CARTESIAN_POINT('',(11.2860583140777,-8.29315518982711,30.5106687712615));
#647=CARTESIAN_POINT('',(11.5124537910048,-7.97592061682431,30.4403758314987));
#648=CARTESIAN_POINT('',(11.9383666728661,-7.32306691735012,30.3035970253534));
#649=CARTESIAN_POINT('',(12.1378819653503,-6.98744634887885,30.2371114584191));
#650=CARTESIAN_POINT('',(12.5086081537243,-6.29978529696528,30.1103101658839));
#651=CARTESIAN_POINT('',(12.6798186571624,-5.94774458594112,30.0499945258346));
#652=CARTESIAN_POINT('',(12.995406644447,-5.22288010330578,29.9365966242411));
#653=CARTESIAN_POINT('',(13.1392387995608,-4.84979462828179,29.8836660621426));
#654=CARTESIAN_POINT('',(13.3947773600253,-4.09145732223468,29.7882483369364));
#655=CARTESIAN_POINT('',(13.5064833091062,-3.70620531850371,29.7457613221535));
#656=CARTESIAN_POINT('',(13.6965670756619,-2.92659573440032,29.6727590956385));
#657=CARTESIAN_POINT('',(13.7749575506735,-2.5322416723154,29.6422393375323));
#658=CARTESIAN_POINT('',(13.8975823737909,-1.73748128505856,29.5942458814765));
#659=CARTESIAN_POINT('',(13.9418190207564,-1.33707536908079,29.5767713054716));
#660=CARTESIAN_POINT('',(13.9938663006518,-0.559809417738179,29.5561870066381));
#661=CARTESIAN_POINT('',(14.0038646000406,-0.183117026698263,29.5522146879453));
#662=CARTESIAN_POINT('',(13.9934656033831,0.569771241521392,29.5563370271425));
#663=CARTESIAN_POINT('',(13.9730696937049,0.945967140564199,29.5644311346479));
#664=CARTESIAN_POINT('',(13.9021052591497,1.69498370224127,29.5924277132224));
#665=CARTESIAN_POINT('',(13.8515420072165,2.06780494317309,29.6123281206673));
#666=CARTESIAN_POINT('',(13.7207650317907,2.80742679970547,29.6633090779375));
#667=CARTESIAN_POINT('',(13.6405512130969,3.17422739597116,29.6943896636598));
#668=CARTESIAN_POINT('',(13.4533898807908,3.89106996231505,29.7659406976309));
#669=CARTESIAN_POINT('',(13.3470863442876,4.24130332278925,29.8061834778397));
#670=CARTESIAN_POINT('',(13.1078098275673,4.93139903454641,29.8952238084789));
#671=CARTESIAN_POINT('',(12.9748373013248,5.27126156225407,29.944021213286));
#672=CARTESIAN_POINT('',(12.6831685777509,5.93885593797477,30.0487555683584));
#673=CARTESIAN_POINT('',(12.5244570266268,6.26658040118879,30.1046967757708));
#674=CARTESIAN_POINT('',(12.1824721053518,6.90792728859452,30.222021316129));
#675=CARTESIAN_POINT('',(11.9991981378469,7.22154936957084,30.2834047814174));
#676=CARTESIAN_POINT('',(11.5981311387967,7.85049346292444,30.413328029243));
#677=CARTESIAN_POINT('',(11.3789684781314,8.16489963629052,30.4820762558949));
#678=CARTESIAN_POINT('',(10.9157841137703,8.77452204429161,30.6211102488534));
#679=CARTESIAN_POINT('',(10.6717592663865,9.06973584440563,30.6913962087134));
#680=CARTESIAN_POINT('',(10.1604769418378,9.63903041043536,30.8307320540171));
#681=CARTESIAN_POINT('',(9.89324525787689,9.91313401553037,30.8997832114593));
#682=CARTESIAN_POINT('',(9.33678786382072,10.4389132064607,31.0337817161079));
#683=CARTESIAN_POINT('',(9.04756946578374,10.6905961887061,31.0987304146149));
#684=CARTESIAN_POINT('',(8.41195971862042,11.199287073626,31.2288880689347));
#685=CARTESIAN_POINT('',(8.0628947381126,11.4532122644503,31.2931658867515));
#686=CARTESIAN_POINT('',(7.34152051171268,11.9284897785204,31.4078348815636));
#687=CARTESIAN_POINT('',(6.96922845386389,12.1498657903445,31.458236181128));
#688=CARTESIAN_POINT('',(6.58646571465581,12.3538847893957,31.4993436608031));
#689=B_SPLINE_CURVE_WITH_KNOTS('',3,(#635,#636,#637,#638,#639,#640,#641,#642,#643,#644,#645,
#646,#647,#648,#649,#650,#651,#652,#653,#654,#655,#656,#657,#658,#659,#660,#661,#662,#663,#664,
#665,#666,#667,#668,#669,#670,#671,#672,#673,#674,#675,#676,#677,#678,#679,#680,#681,#682,#683,
#684,#685,#686,#687,#688),.UNSPECIFIED.,.F.,.F.,(4,2,2,2,2,2,2,2,2,2,2,2,2,2,2,2,2,2,2,2,2,2,2,
2,2,2,4),(0.,1.19034582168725,2.37993730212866,3.56852699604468,4.75730907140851,
5.94405099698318,7.13077727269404,8.31759675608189,9.50443269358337,10.712878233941,
11.9213409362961,13.1293440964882,14.3372659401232,15.4664020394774,16.5954866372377,
17.7243739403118,18.8532648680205,19.956686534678,21.0600894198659,22.1641529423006,
23.2682433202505,24.4350647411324,25.6020338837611,26.767722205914,27.9330245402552,
29.2402088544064,30.5464370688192),.UNSPECIFIED.);
#690=CARTESIAN_POINT('',(14.,0.,29.5537466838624));
#691=VERTEX_POINT('',#690);
#692=EDGE_CURVE('E29',#630,#691,#689,.T.);
#693=ORIENTED_EDGE('',*,*,#692,.T.);
#694=CARTESIAN_POINT('',(75.,0.,-280.25));
#695=DIRECTION('',(0.,1.,0.));
#696=DIRECTION('',(-1.,0.,0.));
#697=AXIS2_PLACEMENT_3D('',#694,#695,#696);
#698=CIRCLE('',#697,315.752056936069);
#699=CARTESIAN_POINT('',(16.6628641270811,0.,30.0661936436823));
#700=VERTEX_POINT('',#699);
#701=EDGE_CURVE('E130',#691,#700,#698,.T.);
#702=ORIENTED_EDGE('',*,*,#701,.T.);
#703=ORIENTED_EDGE('',*,*,#701,.F.);
#704=CARTESIAN_POINT('',(6.58684083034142,12.3536847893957,31.4993033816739));
#705=VERTEX_POINT('',#704);
#706=EDGE_CURVE('E226',#691,#705,#689,.T.);
#707=ORIENTED_EDGE('',*,*,#706,.T.);
#708=CARTESIAN_POINT('',(75.,12.3536847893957,-280.25));
#709=DIRECTION('',(0.,1.,0.));
#710=DIRECTION('',(-1.,0.,0.));
#711=AXIS2_PLACEMENT_3D('',#708,#709,#710);
#712=CIRCLE('',#711,319.167649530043);
#713=CARTESIAN_POINT('',(143.413159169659,12.3536847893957,31.4993033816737));
#714=VERTEX_POINT('',#713);
#715=EDGE_CURVE('E125',#705,#714,#712,.T.);
#716=ORIENTED_EDGE('',*,*,#715,.T.);
#717=CARTESIAN_POINT('',(143.413534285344,12.3538847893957,31.4993436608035));
#718=CARTESIAN_POINT('',(143.064763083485,12.1679719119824,31.4618915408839));
#719=CARTESIAN_POINT('',(142.724675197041,11.9676565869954,31.4167152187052));
#720=CARTESIAN_POINT('',(142.064007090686,11.5401253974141,31.3145631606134));
#721=CARTESIAN_POINT('',(141.743414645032,11.3129266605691,31.2575949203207));
#722=CARTESIAN_POINT('',(141.123692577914,10.8334948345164,31.135502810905));
#723=CARTESIAN_POINT('',(140.824545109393,10.5812829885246,31.0703858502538));
#724=CARTESIAN_POINT('',(140.248917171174,10.0533037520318,30.9353271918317));
#725=CARTESIAN_POINT('',(139.972440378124,9.77753255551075,30.8653847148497));
#726=CARTESIAN_POINT('',(139.444115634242,9.20461258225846,30.7239468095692));
#727=CARTESIAN_POINT('',(139.192226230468,8.90750130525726,30.6524542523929));
#728=CARTESIAN_POINT('',(138.713941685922,8.29315518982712,30.5106687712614));
#729=CARTESIAN_POINT('',(138.487546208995,7.97592061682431,30.4403758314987));
#730=CARTESIAN_POINT('',(138.061633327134,7.32306691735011,30.3035970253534));
#731=CARTESIAN_POINT('',(137.86211803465,6.98744634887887,30.2371114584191));
#732=CARTESIAN_POINT('',(137.491391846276,6.29978529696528,30.1103101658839));
#733=CARTESIAN_POINT('',(137.320181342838,5.94774458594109,30.0499945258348));
#734=CARTESIAN_POINT('',(137.004593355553,5.22288010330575,29.9365966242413));
#735=CARTESIAN_POINT('',(136.860761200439,4.84979462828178,29.8836660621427));
#736=CARTESIAN_POINT('',(136.605222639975,4.09145732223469,29.7882483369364));
#737=CARTESIAN_POINT('',(136.493516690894,3.70620531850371,29.7457613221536));
#738=CARTESIAN_POINT('',(136.303432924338,2.92659573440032,29.6727590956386));
#739=CARTESIAN_POINT('',(136.225042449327,2.53224167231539,29.6422393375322));
#740=CARTESIAN_POINT('',(136.102417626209,1.73748128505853,29.5942458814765));
#741=CARTESIAN_POINT('',(136.058180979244,1.33707536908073,29.5767713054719));
#742=CARTESIAN_POINT('',(136.006133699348,0.55980941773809,29.5561870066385));
#743=CARTESIAN_POINT('',(135.996135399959,0.183117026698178,29.5522146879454));
#744=CARTESIAN_POINT('',(136.006534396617,-0.569771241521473,29.5563370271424));
#745=CARTESIAN_POINT('',(136.026930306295,-0.945967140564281,29.5644311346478));
#746=CARTESIAN_POINT('',(136.09789474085,-1.69498370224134,29.5924277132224));
#747=CARTESIAN_POINT('',(136.148457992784,-2.06780494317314,29.6123281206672));
#748=CARTESIAN_POINT('',(136.279234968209,-2.80742679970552,29.6633090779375));
#749=CARTESIAN_POINT('',(136.359448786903,-3.17422739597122,29.69438966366));
#750=CARTESIAN_POINT('',(136.546610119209,-3.89106996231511,29.7659406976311));
#751=CARTESIAN_POINT('',(136.652913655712,-4.24130332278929,29.8061834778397));
#752=CARTESIAN_POINT('',(136.892190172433,-4.93139903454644,29.8952238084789));
#753=CARTESIAN_POINT('',(137.025162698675,-5.2712615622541,29.944021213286));
#754=CARTESIAN_POINT('',(137.316831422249,-5.93885593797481,30.0487555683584));
#755=CARTESIAN_POINT('',(137.475542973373,-6.26658040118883,30.1046967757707));
#756=CARTESIAN_POINT('',(137.817527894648,-6.90792728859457,30.2220213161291));
#757=CARTESIAN_POINT('',(138.000801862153,-7.2215493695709,30.2834047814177));
#758=CARTESIAN_POINT('',(138.401868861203,-7.85049346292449,30.4133280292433));
#759=CARTESIAN_POINT('',(138.621031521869,-8.16489963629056,30.4820762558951));
#760=CARTESIAN_POINT('',(139.08421588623,-8.77452204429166,30.6211102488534));
#761=CARTESIAN_POINT('',(139.328240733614,-9.06973584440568,30.6913962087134));
#762=CARTESIAN_POINT('',(139.839523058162,-9.63903041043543,30.8307320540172));
#763=CARTESIAN_POINT('',(140.106754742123,-9.91313401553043,30.8997832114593));
#764=CARTESIAN_POINT('',(140.663212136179,-10.4389132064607,31.0337817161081));
#765=CARTESIAN_POINT('',(140.952430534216,-10.6905961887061,31.0987304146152));
#766=CARTESIAN_POINT('',(141.58804028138,-11.199287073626,31.2288880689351));
#767=CARTESIAN_POINT('',(141.937105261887,-11.4532122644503,31.2931658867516));
#768=CARTESIAN_POINT('',(142.658479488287,-11.9284897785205,31.4078348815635));
#769=CARTESIAN_POINT('',(143.030771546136,-12.1498657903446,31.4582361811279));
#770=CARTESIAN_POINT('',(143.413534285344,-12.3538847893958,31.4993436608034));
#771=B_SPLINE_CURVE_WITH_KNOTS('',3,(#717,#718,#719,#720,#721,#722,#723,#724,#725,#726,#727,
#728,#729,#730,#731,#732,#733,#734,#735,#736,#737,#738,#739,#740,#741,#742,#743,#744,#745,#746,
#747,#748,#749,#750,#751,#752,#753,#754,#755,#756,#757,#758,#759,#760,#761,#762,#763,#764,#765,
#766,#767,#768,#769,#770),.UNSPECIFIED.,.F.,.F.,(4,2,2,2,2,2,2,2,2,2,2,2,2,2,2,2,2,2,2,2,2,2,2,
2,2,2,4),(0.,1.19034582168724,2.37993730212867,3.5685269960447,4.75730907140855,
5.94405099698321,7.13077727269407,8.3175967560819,9.50443269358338,10.712878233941,
11.9213409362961,13.1293440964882,14.3372659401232,15.4664020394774,16.5954866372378,
17.7243739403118,18.8532648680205,19.956686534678,21.060089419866,22.1641529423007,
23.2682433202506,24.4350647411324,25.6020338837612,26.7677222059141,27.9330245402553,
29.2402088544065,30.5464370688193),.UNSPECIFIED.);
#772=CARTESIAN_POINT('',(136.,0.,29.5537466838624));
#773=VERTEX_POINT('',#772);
#774=EDGE_CURVE('E209',#714,#773,#771,.T.);
#775=ORIENTED_EDGE('',*,*,#774,.T.);
#776=CARTESIAN_POINT('',(75.,0.,-280.25));
#777=DIRECTION('',(0.,-1.,0.));
#778=DIRECTION('',(1.,0.,0.));
#779=AXIS2_PLACEMENT_3D('',#776,#777,#778);
#780=CIRCLE('',#779,315.752056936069);
#781=CARTESIAN_POINT('',(133.337135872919,0.,30.0661936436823));
#782=VERTEX_POINT('',#781);
#783=EDGE_CURVE('E299',#773,#782,#780,.T.);
#784=ORIENTED_EDGE('',*,*,#783,.T.);
#785=ORIENTED_EDGE('',*,*,#783,.F.);
#786=EDGE_CURVE('E121',#773,#632,#771,.T.);
#787=ORIENTED_EDGE('',*,*,#786,.T.);
#788=EDGE_LOOP('',(#634,#693,#702,#703,#707,#716,#775,#784,#785,#787));
#789=FACE_BOUND('',#788,.T.);
#790=ADVANCED_FACE('F172',(#789),#623,.T.);
#791=CARTESIAN_POINT('',(75.,-11.3586251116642,-280.25));
#792=DIRECTION('',(0.,1.,0.));
#793=DIRECTION('',(-1.,0.,0.));
#794=AXIS2_PLACEMENT_3D('',#791,#792,#793);
#795=TOROIDAL_SURFACE('',#794,321.986650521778,2.98946656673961);
#796=CARTESIAN_POINT('',(75.,-14.,-280.25));
#797=DIRECTION('',(0.,-1.,0.));
#798=DIRECTION('',(1.,0.,0.));
#799=AXIS2_PLACEMENT_3D('',#796,#797,#798);
#800=CIRCLE('',#799,320.586633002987);
#801=CARTESIAN_POINT('',(0.,-14.,31.4402136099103));
#802=VERTEX_POINT('',#801);
#803=CARTESIAN_POINT('',(150.,-14.,31.4402136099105));
#804=VERTEX_POINT('',#803);
#805=EDGE_CURVE('E119',#802,#804,#800,.F.);
#806=ORIENTED_EDGE('',*,*,#805,.F.);
#807=CARTESIAN_POINT('',(-0.127770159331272,-13.9994169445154,31.4083104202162));
#808=CARTESIAN_POINT('',(-0.0318425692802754,-14.0002946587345,31.4331581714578));
#809=CARTESIAN_POINT('',(0.0645811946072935,-14.0001864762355,31.456127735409));
#810=CARTESIAN_POINT('',(0.258215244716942,-13.9979527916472,31.4982760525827));
#811=CARTESIAN_POINT('',(0.355425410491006,-13.9958275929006,31.5174553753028));
#812=CARTESIAN_POINT('',(0.550177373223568,-13.9895236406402,31.5519470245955));
#813=CARTESIAN_POINT('',(0.647717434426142,-13.985350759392,31.5672702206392));
#814=CARTESIAN_POINT('',(0.843186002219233,-13.9749283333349,31.5942693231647));
#815=CARTESIAN_POINT('',(0.941114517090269,-13.96867874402,31.6059451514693));
#816=CARTESIAN_POINT('',(1.23399634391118,-13.9468775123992,31.6357435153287));
#817=CARTESIAN_POINT('',(1.42924756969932,-13.9282350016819,31.6488432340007));
#818=CARTESIAN_POINT('',(1.81929109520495,-13.8826800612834,31.6644750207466));
#819=CARTESIAN_POINT('',(2.0140828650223,-13.8557606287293,31.6669981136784));
#820=CARTESIAN_POINT('',(2.39322253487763,-13.7952021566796,31.6647172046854));
#821=CARTESIAN_POINT('',(2.57763349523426,-13.7619354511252,31.6602497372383));
#822=CARTESIAN_POINT('',(2.94484751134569,-13.6880591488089,31.6470680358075));
#823=CARTESIAN_POINT('',(3.1276502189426,-13.6474480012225,31.6383529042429));
#824=CARTESIAN_POINT('',(3.49147992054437,-13.55893206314,31.6187391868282));
#825=CARTESIAN_POINT('',(3.67250573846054,-13.5110227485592,31.6078392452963));
#826=CARTESIAN_POINT('',(4.03246893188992,-13.4079921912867,31.5855682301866));
#827=CARTESIAN_POINT('',(4.21140608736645,-13.3528701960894,31.5741971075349));
#828=CARTESIAN_POINT('',(4.7450941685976,-13.1766647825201,31.5415835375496));
#829=CARTESIAN_POINT('',(5.09646422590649,-13.0448045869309,31.5218590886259));
#830=CARTESIAN_POINT('',(5.78763142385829,-12.7531887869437,31.4964118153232));
#831=CARTESIAN_POINT('',(6.12743975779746,-12.5934611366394,31.4906750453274));
#832=CARTESIAN_POINT('',(6.7404413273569,-12.2746141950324,31.5014160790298));
#833=CARTESIAN_POINT('',(7.01568474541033,-12.119376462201,31.5145311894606));
#834=CARTESIAN_POINT('',(7.41944943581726,-11.8733620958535,31.5509244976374));
#835=CARTESIAN_POINT('',(7.5526924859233,-11.7890431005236,31.5658735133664));
#836=CARTESIAN_POINT('',(7.81572618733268,-11.6163346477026,31.6021861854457));
#837=CARTESIAN_POINT('',(7.9455147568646,-11.5279428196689,31.6235536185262));
#838=CARTESIAN_POINT('',(8.07335620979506,-11.4376972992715,31.6485332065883));
#839=B_SPLINE_CURVE_WITH_KNOTS('',3,(#807,#808,#809,#810,#811,#812,#813,#814,#815,#816,#817,
#818,#819,#820,#821,#822,#823,#824,#825,#826,#827,#828,#829,#830,#831,#832,#833,#834,#835,#836,
#837,#838),.UNSPECIFIED.,.F.,.F.,(4,2,2,2,2,2,2,2,2,2,2,2,2,2,2,4),(0.,0.297269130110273,
0.594493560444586,0.890870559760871,1.18725391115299,1.77637260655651,2.36599111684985,
2.92808593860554,3.49029958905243,4.05286318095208,4.61548551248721,5.74152477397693,
6.86644092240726,7.81384067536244,8.28880884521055,8.7640570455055),.UNSPECIFIED.);
#840=EDGE_CURVE('E37',#802,#630,#839,.T.);
#841=ORIENTED_EDGE('',*,*,#840,.T.);
#842=ORIENTED_EDGE('',*,*,#633,.T.);
#843=CARTESIAN_POINT('',(141.926643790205,-11.4376972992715,31.6485332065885));
#844=CARTESIAN_POINT('',(142.028695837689,-11.5097344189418,31.6285887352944));
#845=CARTESIAN_POINT('',(142.13199402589,-11.5805980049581,31.6109499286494));
#846=CARTESIAN_POINT('',(142.340868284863,-11.7197881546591,31.5798675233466));
#847=CARTESIAN_POINT('',(142.446443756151,-11.7881153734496,31.5664228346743));
#848=CARTESIAN_POINT('',(142.766034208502,-11.9888676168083,31.5317762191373));
#849=CARTESIAN_POINT('',(142.983211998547,-12.1172743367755,31.5162060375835));
#850=CARTESIAN_POINT('',(143.425199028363,-12.3626911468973,31.497002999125));
#851=CARTESIAN_POINT('',(143.650029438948,-12.4796654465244,31.4934065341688));
#852=CARTESIAN_POINT('',(144.105719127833,-12.7012461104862,31.4953496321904));
#853=CARTESIAN_POINT('',(144.336579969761,-12.8058492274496,31.5008915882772));
#854=CARTESIAN_POINT('',(144.745848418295,-12.9780704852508,31.5161276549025));
#855=CARTESIAN_POINT('',(144.923157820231,-13.0484494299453,31.5244614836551));
#856=CARTESIAN_POINT('',(145.2803945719,-13.1818691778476,31.5434419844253));
#857=CARTESIAN_POINT('',(145.460321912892,-13.2449100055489,31.5540886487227));
#858=CARTESIAN_POINT('',(145.822800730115,-13.3636609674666,31.5763453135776));
#859=CARTESIAN_POINT('',(146.005355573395,-13.4193605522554,31.5879566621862));
#860=CARTESIAN_POINT('',(146.372602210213,-13.5232538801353,31.6105692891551));
#861=CARTESIAN_POINT('',(146.55729371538,-13.5714486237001,31.6215706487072));
#862=CARTESIAN_POINT('',(146.926922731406,-13.6598673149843,31.6410291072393));
#863=CARTESIAN_POINT('',(147.111842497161,-13.700160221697,31.6495085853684));
#864=CARTESIAN_POINT('',(147.48336373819,-13.7732488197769,31.6618828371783));
#865=CARTESIAN_POINT('',(147.669965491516,-13.8060432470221,31.6657768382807));
#866=CARTESIAN_POINT('',(148.043910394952,-13.8639610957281,31.6663849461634));
#867=CARTESIAN_POINT('',(148.231250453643,-13.8891038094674,31.6631172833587));
#868=CARTESIAN_POINT('',(148.606318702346,-13.9317342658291,31.6465823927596));
#869=CARTESIAN_POINT('',(148.794046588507,-13.9492266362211,31.6333212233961));
#870=CARTESIAN_POINT('',(149.077525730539,-13.9699087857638,31.6037889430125));
#871=CARTESIAN_POINT('',(149.173566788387,-13.9759158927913,31.5921252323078));
#872=CARTESIAN_POINT('',(149.365281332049,-13.9859337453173,31.5652764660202));
#873=CARTESIAN_POINT('',(149.460954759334,-13.9899441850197,31.550090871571));
#874=CARTESIAN_POINT('',(149.652292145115,-13.9960106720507,31.5159609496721));
#875=CARTESIAN_POINT('',(149.747952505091,-13.9980546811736,31.4969943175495));
#876=CARTESIAN_POINT('',(149.938492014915,-14.0001896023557,31.4553942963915));
#877=CARTESIAN_POINT('',(150.033371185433,-14.0002805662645,31.432761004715));
#878=CARTESIAN_POINT('',(150.127770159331,-13.9994169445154,31.4083104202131));
#879=B_SPLINE_CURVE_WITH_KNOTS('',3,(#843,#844,#845,#846,#847,#848,#849,#850,#851,#852,#853,
#854,#855,#856,#857,#858,#859,#860,#861,#862,#863,#864,#865,#866,#867,#868,#869,#870,#871,#872,
#873,#874,#875,#876,#877,#878),.UNSPECIFIED.,.F.,.F.,(4,2,2,2,2,2,2,2,2,2,2,2,2,2,2,2,2,4),(0.,
0.379417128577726,0.758735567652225,1.51626575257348,2.27609622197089,3.03612570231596,
3.60880416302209,4.18148071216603,4.75497143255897,5.32838563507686,5.89654814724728,
6.46480637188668,7.03161974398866,7.59808976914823,7.88881623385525,8.17958721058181,
8.47212712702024,8.76465927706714),.UNSPECIFIED.);
#880=EDGE_CURVE('E107',#632,#804,#879,.T.);
#881=ORIENTED_EDGE('',*,*,#880,.T.);
#882=EDGE_LOOP('',(#806,#841,#842,#881));
#883=FACE_BOUND('',#882,.T.);
#884=ADVANCED_FACE('F118',(#883),#795,.T.);
#885=CARTESIAN_POINT('',(75.,11.3586251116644,-280.25));
#886=DIRECTION('',(0.,1.,0.));
#887=DIRECTION('',(-1.,0.,0.));
#888=AXIS2_PLACEMENT_3D('',#885,#886,#887);
#889=TOROIDAL_SURFACE('',#888,321.986650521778,2.98946656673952);
#890=ORIENTED_EDGE('',*,*,#715,.F.);
#891=CARTESIAN_POINT('',(7.54140834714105,11.7952176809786,31.565638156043));
#892=CARTESIAN_POINT('',(7.40732747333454,11.8809488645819,31.549587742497));
#893=CARTESIAN_POINT('',(7.2715550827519,11.9645300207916,31.536640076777));
#894=CARTESIAN_POINT('',(6.99697781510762,12.127148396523,31.5161796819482));
#895=CARTESIAN_POINT('',(6.85817407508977,12.2061872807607,31.5086649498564));
#896=CARTESIAN_POINT('',(6.43813141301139,12.4359219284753,31.493121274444));
#897=CARTESIAN_POINT('',(6.15274197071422,12.5795676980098,31.4920370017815));
#898=CARTESIAN_POINT('',(5.57013688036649,12.8482541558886,31.5027239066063));
#899=CARTESIAN_POINT('',(5.27282963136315,12.9730877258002,31.5146277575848));
#900=CARTESIAN_POINT('',(4.67057378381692,13.2018760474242,31.5455938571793));
#901=CARTESIAN_POINT('',(4.36562291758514,13.3058245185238,31.5646582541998));
#902=CARTESIAN_POINT('',(3.79646683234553,13.4781764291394,31.6002575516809));
#903=CARTESIAN_POINT('',(3.53316119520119,13.5495845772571,31.6167334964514));
#904=CARTESIAN_POINT('',(3.00245979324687,13.6769770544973,31.6448191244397));
#905=CARTESIAN_POINT('',(2.73506284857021,13.7329568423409,31.6564273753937));
#906=CARTESIAN_POINT('',(2.19962485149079,13.8287714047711,31.6679552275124));
#907=CARTESIAN_POINT('',(1.93161308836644,13.8687519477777,31.6679828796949));
#908=CARTESIAN_POINT('',(1.39456119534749,13.9329847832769,31.6483045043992));
#909=CARTESIAN_POINT('',(1.12552308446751,13.9572594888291,31.6286267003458));
#910=CARTESIAN_POINT('',(0.692325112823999,13.9838550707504,31.5749945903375));
#911=CARTESIAN_POINT('',(0.52742740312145,13.9910222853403,31.5493847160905));
#912=CARTESIAN_POINT('',(0.281067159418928,13.9974213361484,31.5027240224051));
#913=CARTESIAN_POINT('',(0.198875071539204,13.9988267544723,31.485734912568));
#914=CARTESIAN_POINT('',(0.0350826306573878,14.0001957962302,31.4490458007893));
#915=CARTESIAN_POINT('',(-0.0465176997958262,14.0001593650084,31.4293456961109));
#916=CARTESIAN_POINT('',(-0.127770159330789,13.9994169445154,31.4083104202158));
#917=B_SPLINE_CURVE_WITH_KNOTS('',3,(#891,#892,#893,#894,#895,#896,#897,#898,#899,#900,#901,
#902,#903,#904,#905,#906,#907,#908,#909,#910,#911,#912,#913,#914,#915,#916),.UNSPECIFIED.,.F.,
.F.,(4,2,2,2,2,2,2,2,2,2,2,2,4),(0.,0.47973203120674,0.959287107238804,1.9165483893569,
2.88368041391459,3.85110284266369,4.67060039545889,5.49033890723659,6.3024288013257,
7.11335722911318,7.61397604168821,7.8657468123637,8.11752712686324),.UNSPECIFIED.);
#918=CARTESIAN_POINT('',(0.,14.,31.4402136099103));
#919=VERTEX_POINT('',#918);
#920=EDGE_CURVE('E219',#705,#919,#917,.T.);
#921=ORIENTED_EDGE('',*,*,#920,.T.);
#922=CARTESIAN_POINT('',(75.,14.,-280.25));
#923=DIRECTION('',(0.,-1.,0.));
#924=DIRECTION('',(1.,0.,0.));
#925=AXIS2_PLACEMENT_3D('',#922,#923,#924);
#926=CIRCLE('',#925,320.586633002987);
#927=CARTESIAN_POINT('',(150.,14.,31.4402136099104));
#928=VERTEX_POINT('',#927);
#929=EDGE_CURVE('E124',#919,#928,#926,.F.);
#930=ORIENTED_EDGE('',*,*,#929,.T.);
#931=CARTESIAN_POINT('',(150.127770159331,13.9994169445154,31.4083104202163));
#932=CARTESIAN_POINT('',(150.031844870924,14.0002946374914,31.4331575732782));
#933=CARTESIAN_POINT('',(149.935423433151,14.0001864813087,31.4561266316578));
#934=CARTESIAN_POINT('',(149.741794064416,13.9979529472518,31.4982741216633));
#935=CARTESIAN_POINT('',(149.64458625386,13.9958278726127,31.5174531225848));
#936=CARTESIAN_POINT('',(149.449838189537,13.9895242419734,31.5519444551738));
#937=CARTESIAN_POINT('',(149.352299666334,13.9853515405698,31.567267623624));
#938=CARTESIAN_POINT('',(149.15683417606,13.9749295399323,31.5942667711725));
#939=CARTESIAN_POINT('',(149.058907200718,13.9686801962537,31.6059426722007));
#940=CARTESIAN_POINT('',(148.766022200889,13.9468792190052,31.6357421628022));
#941=CARTESIAN_POINT('',(148.570766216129,13.9282364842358,31.6488425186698));
#942=CARTESIAN_POINT('',(148.180714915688,13.8826808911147,31.6644749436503));
#943=CARTESIAN_POINT('',(147.985920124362,13.8557611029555,31.6669981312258));
#944=CARTESIAN_POINT('',(147.606757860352,13.7951990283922,31.6647170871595));
#945=CARTESIAN_POINT('',(147.422327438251,13.7619284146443,31.6602487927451));
#946=CARTESIAN_POINT('',(147.055074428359,13.6880426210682,31.6470647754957));
#947=CARTESIAN_POINT('',(146.872252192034,13.6474258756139,31.6383481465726));
#948=CARTESIAN_POINT('',(146.508376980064,13.5588956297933,31.6187309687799));
#949=CARTESIAN_POINT('',(146.327325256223,13.5109773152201,31.6078289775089));
#950=CARTESIAN_POINT('',(145.967310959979,13.4079262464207,31.5855544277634));
#951=CARTESIAN_POINT('',(145.788348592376,13.3527927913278,31.5741818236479));
#952=CARTESIAN_POINT('',(145.254660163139,13.1765764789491,31.5415690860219));
#953=CARTESIAN_POINT('',(144.903321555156,13.0447236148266,31.5218473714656));
#954=CARTESIAN_POINT('',(144.21221553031,12.7531148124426,31.4964100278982));
#955=CARTESIAN_POINT('',(143.872435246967,12.5933912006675,31.4906782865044));
#956=CARTESIAN_POINT('',(143.354776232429,12.3241434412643,31.4997470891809));
#957=CARTESIAN_POINT('',(143.171960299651,12.2237945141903,31.5065651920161));
#958=CARTESIAN_POINT('',(142.811338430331,12.0152666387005,31.529044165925));
#959=CARTESIAN_POINT('',(142.633534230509,11.9070850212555,31.5447080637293));
#960=CARTESIAN_POINT('',(142.458591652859,11.7952176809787,31.5656381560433));
#961=B_SPLINE_CURVE_WITH_KNOTS('',3,(#931,#932,#933,#934,#935,#936,#937,#938,#939,#940,#941,
#942,#943,#944,#945,#946,#947,#948,#949,#950,#951,#952,#953,#954,#955,#956,#957,#958,#959,#960),
.UNSPECIFIED.,.F.,.F.,(4,2,2,2,2,2,2,2,2,2,2,2,2,2,4),(0.,0.297261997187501,0.594479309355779,
0.890851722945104,1.18723047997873,1.77636349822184,2.36599110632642,2.92814549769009,
3.49041983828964,4.05306652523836,4.61576790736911,5.74175322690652,6.86644112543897,
7.49205604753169,8.11788516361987),.UNSPECIFIED.);
#962=EDGE_CURVE('E116',#928,#714,#961,.T.);
#963=ORIENTED_EDGE('',*,*,#962,.T.);
#964=EDGE_LOOP('',(#890,#921,#930,#963));
#965=FACE_BOUND('',#964,.T.);
#966=ADVANCED_FACE('F171',(#965),#889,.T.);
#967=CARTESIAN_POINT('',(132.782867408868,-14.,27.1178404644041));
#968=DIRECTION('',(0.,1.,0.));
#969=DIRECTION('',(-1.,0.,0.));
#970=AXIS2_PLACEMENT_3D('',#967,#968,#969);
#971=PLANE('',#970);
#972=CARTESIAN_POINT('',(75.,-14.,-281.));
#973=DIRECTION('',(0.,1.,0.));
#974=DIRECTION('',(-1.,0.,0.));
#975=AXIS2_PLACEMENT_3D('',#972,#973,#974);
#976=CIRCLE('',#975,323.818614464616);
#977=CARTESIAN_POINT('',(150.,-14.,34.0134839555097));
#978=VERTEX_POINT('',#977);
#979=CARTESIAN_POINT('',(0.,-14.,34.0134839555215));
#980=VERTEX_POINT('',#979);
#981=EDGE_CURVE('E139',#978,#980,#976,.F.);
#982=ORIENTED_EDGE('',*,*,#981,.T.);
#983=DIRECTION('',(0.,0.,-1.));
#984=VECTOR('',#983,1.);
#985=CARTESIAN_POINT('',(0.,-14.,45.));
#986=LINE('',#985,#984);
#987=EDGE_CURVE('E123',#980,#802,#986,.T.);
#988=ORIENTED_EDGE('',*,*,#987,.T.);
#989=ORIENTED_EDGE('',*,*,#805,.T.);
#990=DIRECTION('',(0.,0.,-1.));
#991=VECTOR('',#990,1.);
#992=CARTESIAN_POINT('',(150.,-14.,45.));
#993=LINE('',#992,#991);
#994=EDGE_CURVE('E103',#978,#804,#993,.T.);
#995=ORIENTED_EDGE('',*,*,#994,.F.);
#996=EDGE_LOOP('',(#982,#988,#989,#995));
#997=FACE_BOUND('',#996,.T.);
#998=ADVANCED_FACE('F16',(#997),#971,.F.);
#999=CARTESIAN_POINT('',(132.782867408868,14.,27.1178404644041));
#1000=DIRECTION('',(0.,1.,0.));
#1001=DIRECTION('',(-1.,0.,0.));
#1002=AXIS2_PLACEMENT_3D('',#999,#1000,#1001);
#1003=PLANE('',#1002);
#1004=DIRECTION('',(0.,0.,-1.));
#1005=VECTOR('',#1004,1.);
#1006=CARTESIAN_POINT('',(0.,14.,45.));
#1007=LINE('',#1006,#1005);
#1008=CARTESIAN_POINT('',(0.,14.,34.0134839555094));
#1009=VERTEX_POINT('',#1008);
#1010=EDGE_CURVE('E244',#1009,#919,#1007,.T.);
#1011=ORIENTED_EDGE('',*,*,#1010,.F.);
#1012=CARTESIAN_POINT('',(75.,14.,-281.));
#1013=DIRECTION('',(0.,1.,0.));
#1014=DIRECTION('',(-1.,0.,0.));
#1015=AXIS2_PLACEMENT_3D('',#1012,#1013,#1014);
#1016=CIRCLE('',#1015,323.818614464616);
#1017=CARTESIAN_POINT('',(150.,14.,34.0134839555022));
#1018=VERTEX_POINT('',#1017);
#1019=EDGE_CURVE('E141',#1018,#1009,#1016,.F.);
#1020=ORIENTED_EDGE('',*,*,#1019,.F.);
#1021=DIRECTION('',(0.,0.,-1.));
#1022=VECTOR('',#1021,1.);
#1023=CARTESIAN_POINT('',(150.,14.,45.));
#1024=LINE('',#1023,#1022);
#1025=EDGE_CURVE('E115',#1018,#928,#1024,.T.);
#1026=ORIENTED_EDGE('',*,*,#1025,.T.);
#1027=ORIENTED_EDGE('',*,*,#929,.F.);
#1028=EDGE_LOOP('',(#1011,#1020,#1026,#1027));
#1029=FACE_BOUND('',#1028,.T.);
#1030=ADVANCED_FACE('F289',(#1029),#1003,.T.);
#1031=CARTESIAN_POINT('',(75.,0.,-281.));
#1032=DIRECTION('',(0.,1.,0.));
#1033=DIRECTION('',(-1.,0.,0.));
#1034=AXIS2_PLACEMENT_3D('',#1031,#1032,#1033);
#1035=TOROIDAL_SURFACE('',#1034,260.413164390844,65.5868356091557);
#1036=CARTESIAN_POINT('',(75.,12.5802335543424,-281.));
#1037=DIRECTION('',(0.,1.,0.));
#1038=DIRECTION('',(-1.,0.,0.));
#1039=AXIS2_PLACEMENT_3D('',#1036,#1037,#1038);
#1040=CIRCLE('',#1039,324.78218433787);
#1041=CARTESIAN_POINT('',(-6.14310375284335,12.5802335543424,33.4825336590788));
#1042=VERTEX_POINT('',#1041);
#1043=CARTESIAN_POINT('',(156.143103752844,12.5802335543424,33.482533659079));
#1044=VERTEX_POINT('',#1043);
#1045=EDGE_CURVE('E128',#1042,#1044,#1040,.T.);
#1046=ORIENTED_EDGE('',*,*,#1045,.F.);
#1047=CARTESIAN_POINT('',(-6.14269416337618,12.5804335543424,33.482598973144));
#1048=CARTESIAN_POINT('',(-6.31686116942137,12.4953925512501,33.4548247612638));
#1049=CARTESIAN_POINT('',(-6.48934949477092,12.4066910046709,33.4278961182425));
#1050=CARTESIAN_POINT('',(-6.8306857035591,12.2220861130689,33.3757000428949));
#1051=CARTESIAN_POINT('',(-6.99953357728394,12.1261827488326,33.350432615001));
#1052=CARTESIAN_POINT('',(-7.5001051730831,11.8279004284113,33.2770899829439));
#1053=CARTESIAN_POINT('',(-7.82594622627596,11.6149056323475,33.231460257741));
#1054=CARTESIAN_POINT('',(-8.4589752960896,11.1623051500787,33.1464928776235));
#1055=CARTESIAN_POINT('',(-8.76617886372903,10.9227221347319,33.1071499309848));
#1056=CARTESIAN_POINT('',(-9.35994605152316,10.4184023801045,33.0343086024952));
#1057=CARTESIAN_POINT('',(-9.64651009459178,10.1536661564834,33.0008101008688));
#1058=CARTESIAN_POINT('',(-10.1969811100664,9.6007221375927,32.9391800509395));
#1059=CARTESIAN_POINT('',(-10.460874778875,9.31250075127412,32.9110516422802));
#1060=CARTESIAN_POINT('',(-10.9638372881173,8.71474842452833,32.8596807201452));
#1061=CARTESIAN_POINT('',(-11.2029060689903,8.40521743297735,32.8364382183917));
#1062=CARTESIAN_POINT('',(-11.6543932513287,7.76710051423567,32.7943220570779));
#1063=CARTESIAN_POINT('',(-11.8668165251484,7.438518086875,32.7754475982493));
#1064=CARTESIAN_POINT('',(-12.2634946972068,6.76458299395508,32.7415496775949));
#1065=CARTESIAN_POINT('',(-12.4477497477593,6.41923041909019,32.7265261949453));
#1066=CARTESIAN_POINT('',(-12.7867069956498,5.71428485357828,32.6998520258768));
#1067=CARTESIAN_POINT('',(-12.9414157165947,5.35469502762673,32.6882005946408));
#1068=CARTESIAN_POINT('',(-13.2202084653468,4.62375275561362,32.6678369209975));
#1069=CARTESIAN_POINT('',(-13.3442924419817,4.25240028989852,32.6591246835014));
#1070=CARTESIAN_POINT('',(-13.5609582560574,3.500501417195,32.6442777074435));
#1071=CARTESIAN_POINT('',(-13.6535350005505,3.11995353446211,32.6381433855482));
#1072=CARTESIAN_POINT('',(-13.806494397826,2.35241208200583,32.6281759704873));
#1073=CARTESIAN_POINT('',(-13.8668769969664,1.96541850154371,32.624342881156));
#1074=CARTESIAN_POINT('',(-13.9551442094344,1.18658677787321,32.6187841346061));
#1075=CARTESIAN_POINT('',(-13.9829338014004,0.794737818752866,32.6170646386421));
#1076=CARTESIAN_POINT('',(-14.0054969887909,0.0100863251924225,32.6156663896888));
#1077=CARTESIAN_POINT('',(-14.0002705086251,-0.382716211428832,32.6159876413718));
#1078=CARTESIAN_POINT('',(-13.9568397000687,-1.16647350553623,32.6186872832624));
#1079=CARTESIAN_POINT('',(-13.9186365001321,-1.55742832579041,32.6210656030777));
#1080=CARTESIAN_POINT('',(-13.8095282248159,-2.33472801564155,32.6279986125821));
#1081=CARTESIAN_POINT('',(-13.7386231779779,-2.7210728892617,32.6325533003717));
#1082=CARTESIAN_POINT('',(-13.5645474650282,-3.48673452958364,32.6440619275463));
#1083=CARTESIAN_POINT('',(-13.4613493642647,-3.86604502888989,32.6510179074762));
#1084=CARTESIAN_POINT('',(-13.223453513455,-4.61459736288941,32.667637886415));
#1085=CARTESIAN_POINT('',(-13.088755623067,-4.98383915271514,32.6773018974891));
#1086=CARTESIAN_POINT('',(-12.78883566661,-5.70962936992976,32.6997274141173));
#1087=CARTESIAN_POINT('',(-12.6236125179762,-6.06617734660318,32.7124890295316));
#1088=CARTESIAN_POINT('',(-12.2638597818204,-6.7640105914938,32.7415628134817));
#1089=CARTESIAN_POINT('',(-12.0693306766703,-7.10529611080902,32.7578749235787));
#1090=CARTESIAN_POINT('',(-11.6526576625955,-7.76975916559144,32.7945268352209));
#1091=CARTESIAN_POINT('',(-11.4305479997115,-8.09295844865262,32.8148616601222));
#1092=CARTESIAN_POINT('',(-10.9601821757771,-8.71939421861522,32.8600928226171));
#1093=CARTESIAN_POINT('',(-10.7119258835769,-9.02263060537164,32.8849891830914));
#1094=CARTESIAN_POINT('',(-10.1912162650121,-9.60687954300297,32.939857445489));
#1095=CARTESIAN_POINT('',(-9.91877225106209,-9.88790056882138,32.9698273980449));
#1096=CARTESIAN_POINT('',(-9.35179879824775,-10.4257670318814,33.0353276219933));
#1097=CARTESIAN_POINT('',(-9.05727463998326,-10.6826182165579,33.0708565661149));
#1098=CARTESIAN_POINT('',(-8.34869043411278,-11.2501981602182,33.1605418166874));
#1099=CARTESIAN_POINT('',(-7.92698860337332,-11.5511530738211,33.2169931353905));
#1100=CARTESIAN_POINT('',(-7.27293226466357,-11.965413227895,33.3101461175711));
#1101=CARTESIAN_POINT('',(-7.05146178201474,-12.0972400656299,33.3425888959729));
#1102=CARTESIAN_POINT('',(-6.60188467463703,-12.3483348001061,33.4103892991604));
#1103=CARTESIAN_POINT('',(-6.37377671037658,-12.467600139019,33.4457475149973));
#1104=CARTESIAN_POINT('',(-6.14269416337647,-12.5804335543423,33.482598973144));
#1105=B_SPLINE_CURVE_WITH_KNOTS('',3,(#1047,#1048,#1049,#1050,#1051,#1052,#1053,#1054,#1055,
#1056,#1057,#1058,#1059,#1060,#1061,#1062,#1063,#1064,#1065,#1066,#1067,#1068,#1069,#1070,#1071,
#1072,#1073,#1074,#1075,#1076,#1077,#1078,#1079,#1080,#1081,#1082,#1083,#1084,#1085,#1086,#1087,
#1088,#1089,#1090,#1091,#1092,#1093,#1094,#1095,#1096,#1097,#1098,#1099,#1100,#1101,#1102,#1103,
#1104),.UNSPECIFIED.,.F.,.F.,(4,2,2,2,2,2,2,2,2,2,2,2,2,2,2,2,2,2,2,2,2,2,2,2,2,2,2,2,4),(0.,
0.587309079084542,1.17461972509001,2.34894067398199,3.52226790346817,4.69557108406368,
5.86955815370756,7.04354803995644,8.21732293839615,9.39109148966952,10.5646005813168,
11.7381116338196,12.9118122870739,14.0855148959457,15.2626308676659,16.4397495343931,
17.616827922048,18.7939052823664,19.9719853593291,21.1500706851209,22.3281977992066,
23.5063055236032,24.6829647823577,25.859629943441,27.0358440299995,28.2117777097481,
29.7714879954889,30.5504564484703,31.3295832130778),.UNSPECIFIED.);
#1106=EDGE_CURVE('E316',#1042,#60,#1105,.T.);
#1107=ORIENTED_EDGE('',*,*,#1106,.T.);
#1108=ORIENTED_EDGE('',*,*,#314,.T.);
#1109=CARTESIAN_POINT('',(-6.14310375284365,-12.5802335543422,33.4825336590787));
#1110=VERTEX_POINT('',#1109);
#1111=EDGE_CURVE('E279',#58,#1110,#1105,.T.);
#1112=ORIENTED_EDGE('',*,*,#1111,.T.);
#1113=CARTESIAN_POINT('',(75.,-12.5802335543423,-281.));
#1114=DIRECTION('',(0.,1.,0.));
#1115=DIRECTION('',(-1.,0.,0.));
#1116=AXIS2_PLACEMENT_3D('',#1113,#1114,#1115);
#1117=CIRCLE('',#1116,324.78218433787);
#1118=CARTESIAN_POINT('',(156.143103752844,-12.5802335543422,33.482533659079));
#1119=VERTEX_POINT('',#1118);
#1120=EDGE_CURVE('E136',#1110,#1119,#1117,.T.);
#1121=ORIENTED_EDGE('',*,*,#1120,.T.);
#1122=CARTESIAN_POINT('',(156.142694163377,-12.5804335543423,33.4825989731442));
#1123=CARTESIAN_POINT('',(156.316861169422,-12.49539255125,33.4548247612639));
#1124=CARTESIAN_POINT('',(156.489349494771,-12.4066910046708,33.4278961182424));
#1125=CARTESIAN_POINT('',(156.830685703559,-12.2220861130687,33.3757000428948));
#1126=CARTESIAN_POINT('',(156.999533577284,-12.1261827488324,33.3504326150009));
#1127=CARTESIAN_POINT('',(157.500105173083,-11.8279004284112,33.2770899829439));
#1128=CARTESIAN_POINT('',(157.825946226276,-11.6149056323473,33.231460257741));
#1129=CARTESIAN_POINT('',(158.45897529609,-11.1623051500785,33.1464928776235));
#1130=CARTESIAN_POINT('',(158.766178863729,-10.9227221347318,33.1071499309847));
#1131=CARTESIAN_POINT('',(159.359946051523,-10.4184023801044,33.0343086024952));
#1132=CARTESIAN_POINT('',(159.646510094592,-10.1536661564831,33.000810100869));
#1133=CARTESIAN_POINT('',(160.196981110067,-9.60072213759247,32.9391800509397));
#1134=CARTESIAN_POINT('',(160.460874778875,-9.31250075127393,32.9110516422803));
#1135=CARTESIAN_POINT('',(160.963837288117,-8.71474842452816,32.8596807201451));
#1136=CARTESIAN_POINT('',(161.20290606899,-8.40521743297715,32.8364382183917));
#1137=CARTESIAN_POINT('',(161.654393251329,-7.76710051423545,32.7943220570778));
#1138=CARTESIAN_POINT('',(161.866816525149,-7.43851808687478,32.7754475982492));
#1139=CARTESIAN_POINT('',(162.263494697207,-6.76458299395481,32.7415496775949));
#1140=CARTESIAN_POINT('',(162.447749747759,-6.41923041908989,32.7265261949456));
#1141=CARTESIAN_POINT('',(162.78670699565,-5.71428485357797,32.6998520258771));
#1142=CARTESIAN_POINT('',(162.941415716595,-5.35469502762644,32.6882005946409));
#1143=CARTESIAN_POINT('',(163.220208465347,-4.62375275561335,32.6678369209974));
#1144=CARTESIAN_POINT('',(163.344292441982,-4.25240028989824,32.6591246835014));
#1145=CARTESIAN_POINT('',(163.560958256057,-3.50050141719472,32.6442777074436));
#1146=CARTESIAN_POINT('',(163.653535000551,-3.11995353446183,32.6381433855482));
#1147=CARTESIAN_POINT('',(163.806494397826,-2.35241208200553,32.6281759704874));
#1148=CARTESIAN_POINT('',(163.866876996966,-1.96541850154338,32.6243428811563));
#1149=CARTESIAN_POINT('',(163.955144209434,-1.18658677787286,32.6187841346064));
#1150=CARTESIAN_POINT('',(163.9829338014,-0.794737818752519,32.6170646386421));
#1151=CARTESIAN_POINT('',(164.005496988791,-0.0100863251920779,32.6156663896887));
#1152=CARTESIAN_POINT('',(164.000270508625,0.38271621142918,32.6159876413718));
#1153=CARTESIAN_POINT('',(163.956839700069,1.16647350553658,32.6186872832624));
#1154=CARTESIAN_POINT('',(163.918636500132,1.55742832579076,32.6210656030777));
#1155=CARTESIAN_POINT('',(163.809528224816,2.33472801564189,32.6279986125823));
#1156=CARTESIAN_POINT('',(163.738623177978,2.72107288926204,32.6325533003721));
#1157=CARTESIAN_POINT('',(163.564547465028,3.48673452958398,32.6440619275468));
#1158=CARTESIAN_POINT('',(163.461349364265,3.86604502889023,32.6510179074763));
#1159=CARTESIAN_POINT('',(163.223453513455,4.61459736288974,32.6676378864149));
#1160=CARTESIAN_POINT('',(163.088755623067,4.98383915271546,32.6773018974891));
#1161=CARTESIAN_POINT('',(162.78883566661,5.70962936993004,32.6997274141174));
#1162=CARTESIAN_POINT('',(162.623612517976,6.06617734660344,32.7124890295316));
#1163=CARTESIAN_POINT('',(162.26385978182,6.76401059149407,32.7415628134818));
#1164=CARTESIAN_POINT('',(162.06933067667,7.10529611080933,32.757874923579));
#1165=CARTESIAN_POINT('',(161.652657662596,7.76975916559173,32.7945268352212));
#1166=CARTESIAN_POINT('',(161.430547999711,8.09295844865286,32.8148616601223));
#1167=CARTESIAN_POINT('',(160.960182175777,8.71939421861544,32.860092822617));
#1168=CARTESIAN_POINT('',(160.711925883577,9.02263060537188,32.8849891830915));
#1169=CARTESIAN_POINT('',(160.191216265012,9.60687954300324,32.9398574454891));
#1170=CARTESIAN_POINT('',(159.918772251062,9.88790056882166,32.969827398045));
#1171=CARTESIAN_POINT('',(159.351798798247,10.4257670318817,33.0353276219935));
#1172=CARTESIAN_POINT('',(159.057274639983,10.6826182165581,33.0708565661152));
#1173=CARTESIAN_POINT('',(158.348690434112,11.2501981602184,33.1605418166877));
#1174=CARTESIAN_POINT('',(157.926988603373,11.5511530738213,33.2169931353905));
#1175=CARTESIAN_POINT('',(157.272932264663,11.9654132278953,33.3101461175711));
#1176=CARTESIAN_POINT('',(157.051461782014,12.0972400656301,33.3425888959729));
#1177=CARTESIAN_POINT('',(156.601884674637,12.3483348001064,33.4103892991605));
#1178=CARTESIAN_POINT('',(156.373776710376,12.4676001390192,33.4457475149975));
#1179=CARTESIAN_POINT('',(156.142694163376,12.5804335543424,33.4825989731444));
#1180=B_SPLINE_CURVE_WITH_KNOTS('',3,(#1122,#1123,#1124,#1125,#1126,#1127,#1128,#1129,#1130,
#1131,#1132,#1133,#1134,#1135,#1136,#1137,#1138,#1139,#1140,#1141,#1142,#1143,#1144,#1145,#1146,
#1147,#1148,#1149,#1150,#1151,#1152,#1153,#1154,#1155,#1156,#1157,#1158,#1159,#1160,#1161,#1162,
#1163,#1164,#1165,#1166,#1167,#1168,#1169,#1170,#1171,#1172,#1173,#1174,#1175,#1176,#1177,#1178,
#1179),.UNSPECIFIED.,.F.,.F.,(4,2,2,2,2,2,2,2,2,2,2,2,2,2,2,2,2,2,2,2,2,2,2,2,2,2,2,2,4),(0.,
0.587309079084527,1.17461972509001,2.34894067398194,3.52226790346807,4.69557108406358,
5.86955815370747,7.04354803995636,8.21732293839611,9.39109148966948,10.5646005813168,
11.7381116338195,12.9118122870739,14.0855148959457,15.2626308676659,16.4397495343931,
17.616827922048,18.7939052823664,19.9719853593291,21.1500706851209,22.3281977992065,
23.5063055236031,24.6829647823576,25.859629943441,27.0358440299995,28.2117777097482,
29.7714879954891,30.5504564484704,31.329583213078),.UNSPECIFIED.);
#1181=EDGE_CURVE('E261',#1119,#332,#1180,.T.);
#1182=ORIENTED_EDGE('',*,*,#1181,.T.);
#1183=ORIENTED_EDGE('',*,*,#586,.T.);
#1184=EDGE_CURVE('E250',#330,#1044,#1180,.T.);
#1185=ORIENTED_EDGE('',*,*,#1184,.T.);
#1186=EDGE_LOOP('',(#1046,#1107,#1108,#1112,#1121,#1182,#1183,#1185));
#1187=FACE_BOUND('',#1186,.T.);
#1188=ADVANCED_FACE('F157',(#1187),#1035,.T.);
#1189=CARTESIAN_POINT('',(75.,-12.1608924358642,-281.));
#1190=DIRECTION('',(0.,1.,0.));
#1191=DIRECTION('',(-1.,0.,0.));
#1192=AXIS2_PLACEMENT_3D('',#1189,#1190,#1191);
#1193=TOROIDAL_SURFACE('',#1192,322.636550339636,2.18622785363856);
#1194=ORIENTED_EDGE('',*,*,#1120,.F.);
#1195=CARTESIAN_POINT('',(-6.39844407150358,-12.452305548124,33.4383198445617));
#1196=CARTESIAN_POINT('',(-6.26038036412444,-12.5232534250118,33.4641946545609));
#1197=CARTESIAN_POINT('',(-6.12072373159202,-12.5921052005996,33.4870339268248));
#1198=CARTESIAN_POINT('',(-5.8386239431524,-12.7253591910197,33.5274932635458));
#1199=CARTESIAN_POINT('',(-5.69618190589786,-12.7897631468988,33.5451153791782));
#1200=CARTESIAN_POINT('',(-5.26579264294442,-12.9757045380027,33.5913859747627));
#1201=CARTESIAN_POINT('',(-4.97412440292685,-13.0903099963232,33.6135531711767));
#1202=CARTESIAN_POINT('',(-4.38848088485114,-13.2979762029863,33.6468446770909));
#1203=CARTESIAN_POINT('',(-4.09463461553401,-13.3913779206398,33.6581548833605));
#1204=CARTESIAN_POINT('',(-3.50110644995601,-13.5586632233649,33.677062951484));
#1205=CARTESIAN_POINT('',(-3.20142079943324,-13.6325337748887,33.6846583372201));
#1206=CARTESIAN_POINT('',(-2.66136165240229,-13.7468738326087,33.702131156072));
#1207=CARTESIAN_POINT('',(-2.42175140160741,-13.7910999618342,33.7111941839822));
#1208=CARTESIAN_POINT('',(-1.94110942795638,-13.8669087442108,33.7369308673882));
#1209=CARTESIAN_POINT('',(-1.70007946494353,-13.8985046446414,33.7535965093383));
#1210=CARTESIAN_POINT('',(-1.33692975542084,-13.9365602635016,33.7884155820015));
#1211=CARTESIAN_POINT('',(-1.21483205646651,-13.9477295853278,33.8017755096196));
#1212=CARTESIAN_POINT('',(-0.970874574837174,-13.9668308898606,33.8324088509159));
#1213=CARTESIAN_POINT('',(-0.849014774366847,-13.9747631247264,33.8496819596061));
#1214=CARTESIAN_POINT('',(-0.605441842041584,-13.9874355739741,33.8886790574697));
#1215=CARTESIAN_POINT('',(-0.483730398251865,-13.9921655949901,33.9104169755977));
#1216=CARTESIAN_POINT('',(-0.241092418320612,-13.9984512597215,33.958486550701));
#1217=CARTESIAN_POINT('',(-0.120166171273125,-14.0000057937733,33.9848198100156));
#1218=CARTESIAN_POINT('',(0.000200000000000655,-13.9999999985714,34.0135315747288));
#1219=B_SPLINE_CURVE_WITH_KNOTS('',3,(#1195,#1196,#1197,#1198,#1199,#1200,#1201,#1202,#1203,
#1204,#1205,#1206,#1207,#1208,#1209,#1210,#1211,#1212,#1213,#1214,#1215,#1216,#1217,#1218),
.UNSPECIFIED.,.F.,.F.,(4,2,2,2,2,2,2,2,2,2,2,4),(0.,0.471977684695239,0.94376955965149,
1.88511562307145,2.81003993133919,3.73557991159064,4.46671950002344,5.19709020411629,
5.56700295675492,5.93688688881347,6.30794277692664,6.67912830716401),.UNSPECIFIED.);
#1220=EDGE_CURVE('E292',#1110,#980,#1219,.T.);
#1221=ORIENTED_EDGE('',*,*,#1220,.T.);
#1222=ORIENTED_EDGE('',*,*,#981,.F.);
#1223=CARTESIAN_POINT('',(149.9998,-13.9999999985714,34.0135315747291));
#1224=CARTESIAN_POINT('',(150.127487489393,-14.0000071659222,33.9830630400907));
#1225=CARTESIAN_POINT('',(150.255807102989,-13.9982569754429,33.9552847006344));
#1226=CARTESIAN_POINT('',(150.513301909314,-13.9911780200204,33.9048930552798));
#1227=CARTESIAN_POINT('',(150.642476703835,-13.9858508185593,33.8822774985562));
#1228=CARTESIAN_POINT('',(150.900940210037,-13.9715786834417,33.8420391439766));
#1229=CARTESIAN_POINT('',(151.030227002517,-13.9626462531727,33.8243994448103));
#1230=CARTESIAN_POINT('',(151.28901626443,-13.9411368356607,33.7934060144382));
#1231=CARTESIAN_POINT('',(151.418518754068,-13.9285594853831,33.7800527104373));
#1232=CARTESIAN_POINT('',(151.675699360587,-13.8999477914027,33.7570369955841));
#1233=CARTESIAN_POINT('',(151.803378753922,-13.8839618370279,33.7473276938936));
#1234=CARTESIAN_POINT('',(152.05840851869,-13.8484487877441,33.7305648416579));
#1235=CARTESIAN_POINT('',(152.185758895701,-13.8289217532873,33.7235112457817));
#1236=CARTESIAN_POINT('',(152.567309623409,-13.7650085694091,33.7051367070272));
#1237=CARTESIAN_POINT('',(152.82076695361,-13.7153172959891,33.6966206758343));
#1238=CARTESIAN_POINT('',(153.359513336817,-13.5941210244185,33.6803957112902));
#1239=CARTESIAN_POINT('',(153.644342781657,-13.5205466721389,33.6729624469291));
#1240=CARTESIAN_POINT('',(154.20848215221,-13.3557094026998,33.653799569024));
#1241=CARTESIAN_POINT('',(154.487795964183,-13.2644594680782,33.6420731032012));
#1242=CARTESIAN_POINT('',(155.044293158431,-13.0630793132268,33.6083563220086));
#1243=CARTESIAN_POINT('',(155.321363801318,-12.9526602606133,33.5861985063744));
#1244=CARTESIAN_POINT('',(155.730435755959,-12.7743619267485,33.5409414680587));
#1245=CARTESIAN_POINT('',(155.865853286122,-12.7127407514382,33.5238262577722));
#1246=CARTESIAN_POINT('',(156.134144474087,-12.5854815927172,33.4848323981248));
#1247=CARTESIAN_POINT('',(156.267017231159,-12.5198422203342,33.4629520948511));
#1248=CARTESIAN_POINT('',(156.398444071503,-12.4523055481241,33.4383198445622));
#1249=B_SPLINE_CURVE_WITH_KNOTS('',3,(#1223,#1224,#1225,#1226,#1227,#1228,#1229,#1230,#1231,
#1232,#1233,#1234,#1235,#1236,#1237,#1238,#1239,#1240,#1241,#1242,#1243,#1244,#1245,#1246,#1247,
#1248),.UNSPECIFIED.,.F.,.F.,(4,2,2,2,2,2,2,2,2,2,2,2,4),(0.,0.393762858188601,
0.787353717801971,1.17959112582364,1.57186761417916,1.95890753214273,2.3459408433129,
3.12074053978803,4.00297946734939,4.8845728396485,5.78083206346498,6.22997721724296,
6.67927851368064),.UNSPECIFIED.);
#1250=EDGE_CURVE('E110',#978,#1119,#1249,.T.);
#1251=ORIENTED_EDGE('',*,*,#1250,.T.);
#1252=EDGE_LOOP('',(#1194,#1221,#1222,#1251));
#1253=FACE_BOUND('',#1252,.T.);
#1254=ADVANCED_FACE('F285',(#1253),#1193,.T.);
#1255=CARTESIAN_POINT('',(75.,12.1608924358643,-281.));
#1256=DIRECTION('',(0.,1.,0.));
#1257=DIRECTION('',(-1.,0.,0.));
#1258=AXIS2_PLACEMENT_3D('',#1255,#1256,#1257);
#1259=TOROIDAL_SURFACE('',#1258,322.636550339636,2.18622785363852);
#1260=ORIENTED_EDGE('',*,*,#1019,.T.);
#1261=CARTESIAN_POINT('',(0.000200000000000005,13.9999999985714,34.0135315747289));
#1262=CARTESIAN_POINT('',(-0.127487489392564,14.0000071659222,33.9830630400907));
#1263=CARTESIAN_POINT('',(-0.255807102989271,13.9982569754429,33.9552847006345));
#1264=CARTESIAN_POINT('',(-0.513301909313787,13.9911780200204,33.9048930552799));
#1265=CARTESIAN_POINT('',(-0.642476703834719,13.9858508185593,33.8822774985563));
#1266=CARTESIAN_POINT('',(-0.900940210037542,13.9715786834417,33.8420391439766));
#1267=CARTESIAN_POINT('',(-1.03022700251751,13.9626462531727,33.8243994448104));
#1268=CARTESIAN_POINT('',(-1.28901626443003,13.9411368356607,33.7934060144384));
#1269=CARTESIAN_POINT('',(-1.418518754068,13.9285594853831,33.7800527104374));
#1270=CARTESIAN_POINT('',(-1.6756993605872,13.8999477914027,33.7570369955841));
#1271=CARTESIAN_POINT('',(-1.80337875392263,13.8839618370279,33.7473276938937));
#1272=CARTESIAN_POINT('',(-2.05840851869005,13.8484487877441,33.730564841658));
#1273=CARTESIAN_POINT('',(-2.18575889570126,13.8289217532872,33.7235112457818));
#1274=CARTESIAN_POINT('',(-2.56730962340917,13.765008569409,33.7051367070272));
#1275=CARTESIAN_POINT('',(-2.82076695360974,13.715317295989,33.6966206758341));
#1276=CARTESIAN_POINT('',(-3.35951333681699,13.5941210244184,33.6803957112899));
#1277=CARTESIAN_POINT('',(-3.64434278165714,13.5205466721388,33.672962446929));
#1278=CARTESIAN_POINT('',(-4.20848215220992,13.3557094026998,33.6537995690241));
#1279=CARTESIAN_POINT('',(-4.487795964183,13.2644594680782,33.6420731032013));
#1280=CARTESIAN_POINT('',(-5.04429315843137,13.0630793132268,33.6083563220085));
#1281=CARTESIAN_POINT('',(-5.32136380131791,12.9526602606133,33.5861985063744));
#1282=CARTESIAN_POINT('',(-5.73043575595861,12.7743619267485,33.5409414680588));
#1283=CARTESIAN_POINT('',(-5.86585328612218,12.7127407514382,33.5238262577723));
#1284=CARTESIAN_POINT('',(-6.13414447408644,12.5854815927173,33.4848323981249));
#1285=CARTESIAN_POINT('',(-6.26701723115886,12.5198422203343,33.4629520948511));
#1286=CARTESIAN_POINT('',(-6.39844407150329,12.4523055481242,33.4383198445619));
#1287=B_SPLINE_CURVE_WITH_KNOTS('',3,(#1261,#1262,#1263,#1264,#1265,#1266,#1267,#1268,#1269,
#1270,#1271,#1272,#1273,#1274,#1275,#1276,#1277,#1278,#1279,#1280,#1281,#1282,#1283,#1284,#1285,
#1286),.UNSPECIFIED.,.F.,.F.,(4,2,2,2,2,2,2,2,2,2,2,2,4),(0.,0.393762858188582,
0.787353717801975,1.1795911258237,1.57186761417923,1.95890753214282,2.34594084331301,
3.12074053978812,4.0029794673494,4.88457283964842,5.78083206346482,6.22997721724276,
6.6792785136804),.UNSPECIFIED.);
#1288=EDGE_CURVE('E246',#1009,#1042,#1287,.T.);
#1289=ORIENTED_EDGE('',*,*,#1288,.T.);
#1290=ORIENTED_EDGE('',*,*,#1045,.T.);
#1291=CARTESIAN_POINT('',(156.398444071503,12.4523055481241,33.4383198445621));
#1292=CARTESIAN_POINT('',(156.260380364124,12.5232534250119,33.464194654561));
#1293=CARTESIAN_POINT('',(156.120723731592,12.5921052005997,33.4870339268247));
#1294=CARTESIAN_POINT('',(155.838623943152,12.7253591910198,33.5274932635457));
#1295=CARTESIAN_POINT('',(155.696181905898,12.7897631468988,33.5451153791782));
#1296=CARTESIAN_POINT('',(155.265792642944,12.9757045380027,33.5913859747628));
#1297=CARTESIAN_POINT('',(154.974124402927,13.0903099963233,33.6135531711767));
#1298=CARTESIAN_POINT('',(154.388480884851,13.2979762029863,33.6468446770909));
#1299=CARTESIAN_POINT('',(154.094634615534,13.3913779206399,33.6581548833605));
#1300=CARTESIAN_POINT('',(153.501106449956,13.558663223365,33.6770629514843));
#1301=CARTESIAN_POINT('',(153.201420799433,13.6325337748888,33.6846583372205));
#1302=CARTESIAN_POINT('',(152.661361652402,13.7468738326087,33.7021311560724));
#1303=CARTESIAN_POINT('',(152.421751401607,13.7910999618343,33.7111941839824));
#1304=CARTESIAN_POINT('',(151.941109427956,13.8669087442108,33.7369308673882));
#1305=CARTESIAN_POINT('',(151.700079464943,13.8985046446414,33.7535965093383));
#1306=CARTESIAN_POINT('',(151.336929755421,13.9365602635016,33.7884155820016));
#1307=CARTESIAN_POINT('',(151.214832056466,13.9477295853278,33.8017755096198));
#1308=CARTESIAN_POINT('',(150.970874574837,13.9668308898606,33.8324088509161));
#1309=CARTESIAN_POINT('',(150.849014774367,13.9747631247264,33.8496819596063));
#1310=CARTESIAN_POINT('',(150.605441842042,13.9874355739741,33.8886790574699));
#1311=CARTESIAN_POINT('',(150.483730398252,13.9921655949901,33.9104169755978));
#1312=CARTESIAN_POINT('',(150.241092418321,13.9984512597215,33.9584865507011));
#1313=CARTESIAN_POINT('',(150.120166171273,14.0000057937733,33.9848198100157));
#1314=CARTESIAN_POINT('',(149.9998,13.9999999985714,34.0135315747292));
#1315=B_SPLINE_CURVE_WITH_KNOTS('',3,(#1291,#1292,#1293,#1294,#1295,#1296,#1297,#1298,#1299,
#1300,#1301,#1302,#1303,#1304,#1305,#1306,#1307,#1308,#1309,#1310,#1311,#1312,#1313,#1314),
.UNSPECIFIED.,.F.,.F.,(4,2,2,2,2,2,2,2,2,2,2,4),(0.,0.471977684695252,0.943769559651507,
1.88511562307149,2.81003993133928,3.73557991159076,4.4667195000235,5.19709020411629,
5.56700295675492,5.93688688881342,6.30794277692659,6.67912830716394),.UNSPECIFIED.);
#1316=EDGE_CURVE('E262',#1044,#1018,#1315,.T.);
#1317=ORIENTED_EDGE('',*,*,#1316,.T.);
#1318=EDGE_LOOP('',(#1260,#1289,#1290,#1317));
#1319=FACE_BOUND('',#1318,.T.);
#1320=ADVANCED_FACE('F215',(#1319),#1259,.T.);
#1321=CARTESIAN_POINT('',(150.,0.,45.));
#1322=DIRECTION('',(0.,0.,-1.));
#1323=DIRECTION('',(-1.,0.,0.));
#1324=AXIS2_PLACEMENT_3D('',#1321,#1322,#1323);
#1325=CYLINDRICAL_SURFACE('',#1324,14.);
#1326=ORIENTED_EDGE('',*,*,#994,.T.);
#1327=ORIENTED_EDGE('',*,*,#880,.F.);
#1328=ORIENTED_EDGE('',*,*,#786,.F.);
#1329=ORIENTED_EDGE('',*,*,#774,.F.);
#1330=ORIENTED_EDGE('',*,*,#962,.F.);
#1331=ORIENTED_EDGE('',*,*,#1025,.F.);
#1332=ORIENTED_EDGE('',*,*,#1316,.F.);
#1333=ORIENTED_EDGE('',*,*,#1184,.F.);
#1334=ORIENTED_EDGE('',*,*,#333,.T.);
#1335=ORIENTED_EDGE('',*,*,#1181,.F.);
#1336=ORIENTED_EDGE('',*,*,#1250,.F.);
#1337=EDGE_LOOP('',(#1326,#1327,#1328,#1329,#1330,#1331,#1332,#1333,#1334,#1335,#1336));
#1338=FACE_BOUND('',#1337,.T.);
#1339=ORIENTED_EDGE('',*,*,#614,.F.);
#1340=EDGE_LOOP('',(#1339));
#1341=FACE_BOUND('',#1340,.T.);
#1342=ADVANCED_FACE('F105',(#1338,#1341),#1325,.T.);
#1343=CARTESIAN_POINT('',(0.,0.,45.));
#1344=DIRECTION('',(0.,0.,-1.));
#1345=DIRECTION('',(-1.,0.,0.));
#1346=AXIS2_PLACEMENT_3D('',#1343,#1344,#1345);
#1347=CYLINDRICAL_SURFACE('',#1346,14.);
#1348=ORIENTED_EDGE('',*,*,#1010,.T.);
#1349=ORIENTED_EDGE('',*,*,#920,.F.);
#1350=ORIENTED_EDGE('',*,*,#706,.F.);
#1351=ORIENTED_EDGE('',*,*,#692,.F.);
#1352=ORIENTED_EDGE('',*,*,#840,.F.);
#1353=ORIENTED_EDGE('',*,*,#987,.F.);
#1354=ORIENTED_EDGE('',*,*,#1220,.F.);
#1355=ORIENTED_EDGE('',*,*,#1111,.F.);
#1356=ORIENTED_EDGE('',*,*,#61,.T.);
#1357=ORIENTED_EDGE('',*,*,#1106,.F.);
#1358=ORIENTED_EDGE('',*,*,#1288,.F.);
#1359=EDGE_LOOP('',(#1348,#1349,#1350,#1351,#1352,#1353,#1354,#1355,#1356,#1357,#1358));
#1360=FACE_BOUND('',#1359,.T.);
#1361=ORIENTED_EDGE('',*,*,#42,.T.);
#1362=EDGE_LOOP('',(#1361));
#1363=FACE_BOUND('',#1362,.T.);
#1364=ADVANCED_FACE('F198',(#1360,#1363),#1347,.T.);
#1365=CARTESIAN_POINT('',(150.,0.,13.));
#1366=DIRECTION('',(0.,0.,-1.));
#1367=DIRECTION('',(-1.,0.,0.));
#1368=AXIS2_PLACEMENT_3D('',#1365,#1366,#1367);
#1369=CYLINDRICAL_SURFACE('',#1368,4.);
#1370=CARTESIAN_POINT('',(150.,0.,13.));
#1371=DIRECTION('',(0.,0.,-1.));
#1372=DIRECTION('',(-1.,0.,0.));
#1373=AXIS2_PLACEMENT_3D('',#1370,#1371,#1372);
#1374=CIRCLE('',#1373,4.);
#1375=CARTESIAN_POINT('',(146.,0.,13.));
#1376=VERTEX_POINT('',#1375);
#1377=EDGE_CURVE('E369',#1376,#1376,#1374,.T.);
#1378=ORIENTED_EDGE('',*,*,#1377,.F.);
#1379=EDGE_LOOP('',(#1378));
#1380=FACE_BOUND('',#1379,.T.);
#1381=ORIENTED_EDGE('',*,*,#603,.T.);
#1382=EDGE_LOOP('',(#1381));
#1383=FACE_BOUND('',#1382,.T.);
#1384=ADVANCED_FACE('F343',(#1380,#1383),#1369,.F.);
#1385=CARTESIAN_POINT('',(150.,0.,13.));
#1386=DIRECTION('',(0.,0.,-1.));
#1387=DIRECTION('',(-1.,0.,0.));
#1388=AXIS2_PLACEMENT_3D('',#1385,#1386,#1387);
#1389=PLANE('',#1388);
#1390=ORIENTED_EDGE('',*,*,#1377,.T.);
#1391=EDGE_LOOP('',(#1390));
#1392=FACE_BOUND('',#1391,.T.);
#1393=ADVANCED_FACE('F347',(#1392),#1389,.T.);
#1394=CARTESIAN_POINT('',(0.,0.,13.));
#1395=DIRECTION('',(0.,0.,-1.));
#1396=DIRECTION('',(-1.,0.,0.));
#1397=AXIS2_PLACEMENT_3D('',#1394,#1395,#1396);
#1398=CYLINDRICAL_SURFACE('',#1397,4.);
#1399=CARTESIAN_POINT('',(0.,0.,13.));
#1400=DIRECTION('',(0.,0.,-1.));
#1401=DIRECTION('',(-1.,0.,0.));
#1402=AXIS2_PLACEMENT_3D('',#1399,#1400,#1401);
#1403=CIRCLE('',#1402,4.);
#1404=CARTESIAN_POINT('',(-4.,0.,13.));
#1405=VERTEX_POINT('',#1404);
#1406=EDGE_CURVE('E227',#1405,#1405,#1403,.T.);
#1407=ORIENTED_EDGE('',*,*,#1406,.F.);
#1408=EDGE_LOOP('',(#1407));
#1409=FACE_BOUND('',#1408,.T.);
#1410=ORIENTED_EDGE('',*,*,#31,.T.);
#1411=EDGE_LOOP('',(#1410));
#1412=FACE_BOUND('',#1411,.T.);
#1413=ADVANCED_FACE('F352',(#1409,#1412),#1398,.F.);
#1414=CARTESIAN_POINT('',(0.,0.,13.));
#1415=DIRECTION('',(0.,0.,-1.));
#1416=DIRECTION('',(-1.,0.,0.));
#1417=AXIS2_PLACEMENT_3D('',#1414,#1415,#1416);
#1418=PLANE('',#1417);
#1419=ORIENTED_EDGE('',*,*,#1406,.T.);
#1420=EDGE_LOOP('',(#1419));
#1421=FACE_BOUND('',#1420,.T.);
#1422=ADVANCED_FACE('F360',(#1421),#1418,.T.);
#1423=CLOSED_SHELL('',(#46,#318,#590,#618,#790,#884,#966,#998,#1030,#1188,#1254,#1320,#1342,
#1364,#1384,#1393,#1413,#1422));
#1424=MANIFOLD_SOLID_BREP('B1',#1423);
#1425=ADVANCED_BREP_SHAPE_REPRESENTATION('',(#18,#1424),#14);
#1426=SHAPE_DEFINITION_REPRESENTATION(#9,#1425);
ENDSEC;
END-ISO-10303-21;
